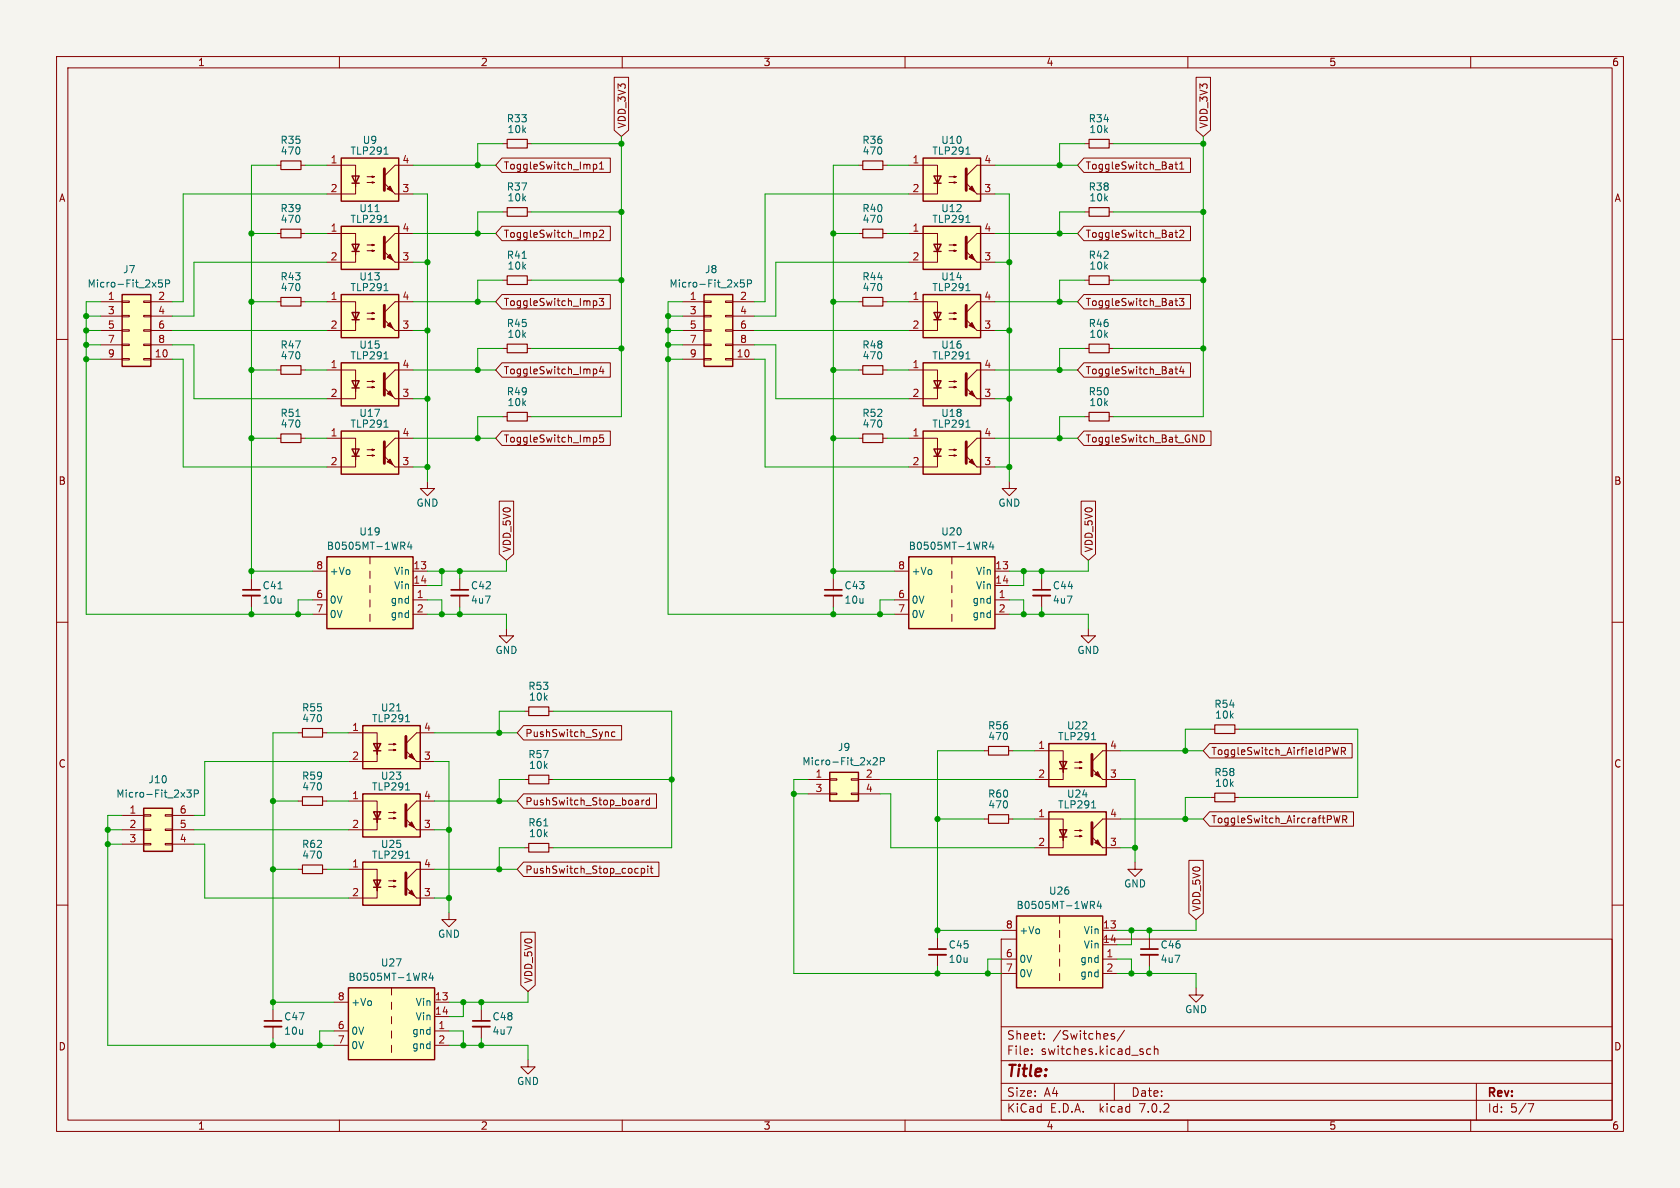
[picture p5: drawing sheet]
<svg xmlns="http://www.w3.org/2000/svg" width="297mm" height="210mm" viewBox="0 0 297 210" stroke-linecap="round" stroke-linejoin="round" font-family="sans-serif">
<defs><g id="words">
<text font-size="2.8" fill="#840000" x="178" y="190.8">Title:</text>
<g font-size="2.1" fill="#840000">
<text x="178" y="183.9">Sheet:</text>
<text x="186.2" y="183.9">/Switches/</text>
<text x="178" y="186.6">File:</text>
<text x="184" y="186.6">switches.kicad_sch</text>
<text x="178" y="196.8">KiCad</text>
<text x="178" y="194">Size:</text>
<text x="184.6" y="194">A4</text>
<text x="185.7" y="196.8">E.D.A.</text>
<text x="194.4" y="196.8">kicad</text>
<text x="200" y="194">Date:</text>
<text x="201.5" y="196.8">7.0.2</text>
<text x="263" y="194.2">Rev:</text>
<text x="263" y="196.8">Id:</text>
<text x="267" y="196.8">5/7</text>
</g>
<g font-size="1.8" fill="#840000">
<text x="35" y="11.8">1</text>
<text x="85" y="11.8">2</text>
<text x="135" y="11.8">3</text>
<text x="185" y="11.8">4</text>
<text x="235" y="11.8">5</text>
<text x="285" y="11.8">6</text>
<text x="110.8" y="22.7" transform="rotate(-90 110.8 22.7)">VDD_3V3</text>
<text x="213.6" y="22.7" transform="rotate(-90 213.6 22.7)">VDD_3V3</text>
<text x="10.4" y="35.8">A</text>
<text x="89.1" y="30.1">ToggleSwitch_Imp1</text>
<text x="191.9" y="30.1">ToggleSwitch_Bat1</text>
<text x="285.4" y="35.8">A</text>
<text x="89.1" y="42.2">ToggleSwitch_Imp2</text>
<text x="191.9" y="42.2">ToggleSwitch_Bat2</text>
<text x="89.1" y="54.3">ToggleSwitch_Imp3</text>
<text x="191.9" y="54.3">ToggleSwitch_Bat3</text>
<text x="89.1" y="66.3">ToggleSwitch_Imp4</text>
<text x="191.9" y="66.3">ToggleSwitch_Bat4</text>
<text x="89.1" y="78.4">ToggleSwitch_Imp5</text>
<text x="191.9" y="78.4">ToggleSwitch_Bat_GND</text>
<text x="10.3" y="85.8">B</text>
<text x="285.3" y="85.8">B</text>
<text x="90.5" y="97.6" transform="rotate(-90 90.5 97.6)">VDD_5V0</text>
<text x="193.3" y="97.6" transform="rotate(-90 193.3 97.6)">VDD_5V0</text>
<text x="92.9" y="130.5">PushSwitch_Sync</text>
<text x="10.3" y="135.8">C</text>
<text x="214.2" y="133.6">ToggleSwitch_AirfieldPWR</text>
<text x="285.3" y="135.8">C</text>
<text x="92.9" y="142.5">PushSwitch_Stop_board</text>
<text x="214.2" y="145.7">ToggleSwitch_AircraftPWR</text>
<text x="92.9" y="154.6">PushSwitch_Stop_cocpit</text>
<text x="212.4" y="161.1" transform="rotate(-90 212.4 161.1)">VDD_5V0</text>
<text x="94.3" y="173.8" transform="rotate(-90 94.3 173.8)">VDD_5V0</text>
<text x="10.3" y="185.8">D</text>
<text x="285.3" y="185.8">D</text>
<text x="35" y="199.8">1</text>
<text x="85" y="199.8">2</text>
<text x="135" y="199.8">3</text>
<text x="185" y="199.8">4</text>
<text x="235" y="199.8">5</text>
<text x="285" y="199.8">6</text>
</g>
<g font-size="1.8" fill="#006464">
<text x="89.5" y="21.8">R33</text>
<text x="89.7" y="23.7">10k</text>
<text x="192.4" y="21.8">R34</text>
<text x="192.5" y="23.7">10k</text>
<text x="49.5" y="25.6">R35</text>
<text x="49.6" y="27.5">470</text>
<text x="61.9" y="27.5">TLP291</text>
<text x="64.1" y="25.6">U9</text>
<text x="152.4" y="25.6">R36</text>
<text x="152.4" y="27.5">470</text>
<text x="164.8" y="27.5">TLP291</text>
<text x="166.3" y="25.6">U10</text>
<text x="89.5" y="33.8">R37</text>
<text x="89.7" y="35.8">10k</text>
<text x="192.4" y="33.8">R38</text>
<text x="192.5" y="35.8">10k</text>
<text x="49.5" y="37.7">R39</text>
<text x="49.6" y="39.6">470</text>
<text x="61.9" y="39.6">TLP291</text>
<text x="63.5" y="37.7">U11</text>
<text x="152.4" y="37.7">R40</text>
<text x="152.4" y="39.6">470</text>
<text x="164.8" y="39.6">TLP291</text>
<text x="166.3" y="37.7">U12</text>
<text x="89.5" y="45.9">R41</text>
<text x="89.7" y="47.8">10k</text>
<text x="192.4" y="45.9">R42</text>
<text x="192.5" y="47.8">10k</text>
<text x="15.4" y="51">Micro-Fit_2x5P</text>
<text x="21.7" y="48.5">J7</text>
<text x="49.5" y="49.7">R43</text>
<text x="49.6" y="51.6">470</text>
<text x="61.9" y="51.6">TLP291</text>
<text x="63.5" y="49.7">U13</text>
<text x="118.3" y="51">Micro-Fit_2x5P</text>
<text x="124.6" y="48.5">J8</text>
<text x="152.4" y="49.7">R44</text>
<text x="152.4" y="51.6">470</text>
<text x="164.8" y="51.6">TLP291</text>
<text x="166.3" y="49.7">U14</text>
<text x="89.5" y="58">R45</text>
<text x="89.7" y="59.9">10k</text>
<text x="192.4" y="58">R46</text>
<text x="192.5" y="59.9">10k</text>
<text x="49.5" y="61.8">R47</text>
<text x="49.6" y="63.7">470</text>
<text x="61.9" y="63.7">TLP291</text>
<text x="63.5" y="61.8">U15</text>
<text x="152.4" y="61.8">R48</text>
<text x="152.4" y="63.7">470</text>
<text x="164.8" y="63.7">TLP291</text>
<text x="166.3" y="61.8">U16</text>
<text x="89.5" y="70">R49</text>
<text x="89.7" y="71.9">10k</text>
<text x="192.4" y="70">R50</text>
<text x="192.5" y="71.9">10k</text>
<text x="49.5" y="73.9">R51</text>
<text x="49.6" y="75.8">470</text>
<text x="61.9" y="75.8">TLP291</text>
<text x="63.5" y="73.9">U17</text>
<text x="152.4" y="73.9">R52</text>
<text x="152.4" y="75.8">470</text>
<text x="164.8" y="75.8">TLP291</text>
<text x="166.3" y="73.9">U18</text>
<text x="73.6" y="89.7">GND</text>
<text x="176.4" y="89.7">GND</text>
<text x="63.5" y="94.8">U19</text>
<text x="166.3" y="94.8">U20</text>
<text x="57.7" y="97.3">B0505MT-1WR4</text>
<text x="58.3" y="101.8">+Vo</text>
<text x="69.5" y="101.8">Vin</text>
<text x="160.6" y="97.3">B0505MT-1WR4</text>
<text x="161.2" y="101.8">+Vo</text>
<text x="172.4" y="101.8">Vin</text>
<text x="46.4" y="104.3">C41</text>
<text x="46.4" y="106.9">10u</text>
<text x="58.3" y="106.9">0V</text>
<text x="68.9" y="106.9">gnd</text>
<text x="69.5" y="104.3">Vin</text>
<text x="83.2" y="104.3">C42</text>
<text x="83.2" y="106.9">4u7</text>
<text x="149.2" y="104.3">C43</text>
<text x="149.2" y="106.9">10u</text>
<text x="161.2" y="106.9">0V</text>
<text x="171.8" y="106.9">gnd</text>
<text x="172.4" y="104.3">Vin</text>
<text x="186.1" y="104.3">C44</text>
<text x="186.1" y="106.9">4u7</text>
<text x="58.3" y="109.4">0V</text>
<text x="68.9" y="109.4">gnd</text>
<text x="161.2" y="109.4">0V</text>
<text x="171.8" y="109.4">gnd</text>
<text x="87.5" y="115.8">GND</text>
<text x="190.4" y="115.8">GND</text>
<text x="53.3" y="125.9">R55</text>
<text x="67.3" y="125.9">U21</text>
<text x="93.3" y="122.1">R53</text>
<text x="93.5" y="124">10k</text>
<text x="214.6" y="125.3">R54</text>
<text x="53.4" y="127.8">470</text>
<text x="65.7" y="127.8">TLP291</text>
<text x="174.6" y="129.1">R56</text>
<text x="174.7" y="131">470</text>
<text x="187" y="131">TLP291</text>
<text x="188.6" y="129.1">U22</text>
<text x="214.7" y="127.2">10k</text>
<text x="53.3" y="138">R59</text>
<text x="67.3" y="138">U23</text>
<text x="93.3" y="134.2">R57</text>
<text x="93.5" y="136.1">10k</text>
<text x="141.8" y="135.4">Micro-Fit_2x2P</text>
<text x="148.1" y="132.9">J9</text>
<text x="214.6" y="137.4">R58</text>
<text x="20.5" y="141.2">Micro-Fit_2x3P</text>
<text x="26.2" y="138.6">J10</text>
<text x="53.4" y="139.9">470</text>
<text x="65.7" y="139.9">TLP291</text>
<text x="174.6" y="141.2">R60</text>
<text x="174.7" y="143.1">470</text>
<text x="187" y="143.1">TLP291</text>
<text x="188.6" y="141.2">U24</text>
<text x="214.7" y="139.3">10k</text>
<text x="93.3" y="146.2">R61</text>
<text x="93.5" y="148.1">10k</text>
<text x="53.3" y="150.1">R62</text>
<text x="53.4" y="152">470</text>
<text x="65.7" y="152">TLP291</text>
<text x="67.3" y="150.1">U25</text>
<text x="179.6" y="160.8">B0505MT-1WR4</text>
<text x="185.4" y="158.3">U26</text>
<text x="198.7" y="157">GND</text>
<text x="77.4" y="165.9">GND</text>
<text x="167.6" y="167.8">C45</text>
<text x="180.2" y="165.3">+Vo</text>
<text x="191.5" y="165.3">Vin</text>
<text x="191.5" y="167.8">Vin</text>
<text x="205.1" y="167.8">C46</text>
<text x="61.5" y="173.5">B0505MT-1WR4</text>
<text x="67.3" y="171">U27</text>
<text x="167.6" y="170.4">10u</text>
<text x="180.2" y="170.4">0V</text>
<text x="180.2" y="172.9">0V</text>
<text x="190.9" y="170.4">gnd</text>
<text x="190.9" y="172.9">gnd</text>
<text x="205.1" y="170.4">4u7</text>
<text x="62.1" y="178">+Vo</text>
<text x="73.4" y="178">Vin</text>
<text x="209.5" y="179.3">GND</text>
<text x="50.2" y="180.5">C47</text>
<text x="50.2" y="183.1">10u</text>
<text x="62.1" y="183.1">0V</text>
<text x="62.1" y="185.6">0V</text>
<text x="72.8" y="183.1">gnd</text>
<text x="72.8" y="185.6">gnd</text>
<text x="73.4" y="180.5">Vin</text>
<text x="87" y="180.5">C48</text>
<text x="87" y="183.1">4u7</text>
<text x="91.3" y="192">GND</text>
</g>
<g font-size="1.8" fill="#a90000">
<text x="58.4" y="29">1</text>
<text x="71.1" y="29">4</text>
<text x="161.3" y="29">1</text>
<text x="174" y="29">4</text>
<text x="58.4" y="34">2</text>
<text x="71.1" y="34">3</text>
<text x="161.3" y="34">2</text>
<text x="174" y="34">3</text>
<text x="58.4" y="41">1</text>
<text x="71.1" y="41">4</text>
<text x="161.3" y="41">1</text>
<text x="174" y="41">4</text>
<text x="58.4" y="46.1">2</text>
<text x="71.1" y="46.1">3</text>
<text x="161.3" y="46.1">2</text>
<text x="174" y="46.1">3</text>
<text x="19" y="53.1">1</text>
<text x="27.9" y="53.1">2</text>
<text x="58.4" y="53.1">1</text>
<text x="71.1" y="53.1">4</text>
<text x="121.9" y="53.1">1</text>
<text x="130.8" y="53.1">2</text>
<text x="161.3" y="53.1">1</text>
<text x="174" y="53.1">4</text>
<text x="19" y="55.6">3</text>
<text x="19" y="58.2">5</text>
<text x="27.9" y="55.6">4</text>
<text x="27.9" y="58.2">6</text>
<text x="58.4" y="58.2">2</text>
<text x="71.1" y="58.2">3</text>
<text x="121.9" y="55.6">3</text>
<text x="121.9" y="58.2">5</text>
<text x="130.8" y="55.6">4</text>
<text x="130.8" y="58.2">6</text>
<text x="161.3" y="58.2">2</text>
<text x="174" y="58.2">3</text>
<text x="19" y="60.7">7</text>
<text x="19" y="63.2">9</text>
<text x="27.3" y="63.2">10</text>
<text x="27.9" y="60.7">8</text>
<text x="58.4" y="65.2">1</text>
<text x="71.1" y="65.2">4</text>
<text x="121.9" y="60.7">7</text>
<text x="121.9" y="63.2">9</text>
<text x="130.2" y="63.2">10</text>
<text x="130.8" y="60.7">8</text>
<text x="161.3" y="65.2">1</text>
<text x="174" y="65.2">4</text>
<text x="58.4" y="70.2">2</text>
<text x="71.1" y="70.2">3</text>
<text x="161.3" y="70.2">2</text>
<text x="174" y="70.2">3</text>
<text x="58.4" y="77.2">1</text>
<text x="71.1" y="77.2">4</text>
<text x="161.3" y="77.2">1</text>
<text x="174" y="77.2">4</text>
<text x="58.4" y="82.3">2</text>
<text x="71.1" y="82.3">3</text>
<text x="161.3" y="82.3">2</text>
<text x="174" y="82.3">3</text>
<text x="55.8" y="100.7">8</text>
<text x="73" y="100.7">13</text>
<text x="158.7" y="100.7">8</text>
<text x="175.9" y="100.7">13</text>
<text x="55.8" y="105.8">6</text>
<text x="73" y="103.3">14</text>
<text x="73.6" y="105.8">1</text>
<text x="158.7" y="105.8">6</text>
<text x="175.9" y="103.3">14</text>
<text x="176.5" y="105.8">1</text>
<text x="55.8" y="108.3">7</text>
<text x="73.6" y="108.3">2</text>
<text x="158.7" y="108.3">7</text>
<text x="176.5" y="108.3">2</text>
<text x="62.2" y="129.3">1</text>
<text x="74.9" y="129.3">4</text>
<text x="62.2" y="134.4">2</text>
<text x="74.9" y="134.4">3</text>
<text x="144.1" y="137.5">1</text>
<text x="153" y="137.5">2</text>
<text x="183.5" y="132.5">1</text>
<text x="183.5" y="137.5">2</text>
<text x="196.2" y="137.5">3</text>
<text x="196.2" y="132.5">4</text>
<text x="22.8" y="143.9">1</text>
<text x="31.7" y="143.9">6</text>
<text x="62.2" y="141.4">1</text>
<text x="74.9" y="141.4">4</text>
<text x="144.1" y="140.1">3</text>
<text x="153" y="140.1">4</text>
<text x="22.8" y="146.4">2</text>
<text x="22.8" y="149">3</text>
<text x="31.7" y="149">4</text>
<text x="31.7" y="146.4">5</text>
<text x="62.2" y="146.4">2</text>
<text x="74.9" y="146.4">3</text>
<text x="183.5" y="144.5">1</text>
<text x="183.5" y="149.6">2</text>
<text x="196.2" y="149.6">3</text>
<text x="196.2" y="144.5">4</text>
<text x="62.2" y="153.4">1</text>
<text x="74.9" y="153.4">4</text>
<text x="62.2" y="158.5">2</text>
<text x="74.9" y="158.5">3</text>
<text x="177.8" y="164.2">8</text>
<text x="194.9" y="164.2">13</text>
<text x="194.9" y="166.8">14</text>
<text x="177.8" y="169.3">6</text>
<text x="177.8" y="171.8">7</text>
<text x="195.5" y="169.3">1</text>
<text x="195.5" y="171.8">2</text>
<text x="59.7" y="176.9">8</text>
<text x="76.8" y="176.9">13</text>
<text x="76.8" y="179.5">14</text>
<text x="59.7" y="182">6</text>
<text x="59.7" y="184.5">7</text>
<text x="77.4" y="182">1</text>
<text x="77.4" y="184.5">2</text>
</g>
</g></defs>
<path d="M0 0h297v210h-297z" fill="#f5f4ef" stroke="#f5f4ef" stroke-width=".18"/>
<g fill="none" stroke="#840000" stroke-width=".18">
<path d="M10 10h277v190h-277zM12 12h273v186h-273zM60 10v2M108.6 13.7h2.5v9.3l-1.2 1.1-1.3-1.1zM110 10v2M160 10v2M210 10v2M211.5 13.7h2.5v9.3l-1.3 1.1-1.2-1.1zM260 10v2M48.9 29.2h.8M53.2 29.2h.8M57.8 29.2h5.1v3.8v-1.9"/>
<path d="M62.9 32.4v1.9h-5.1M64.9 32.3h1.3l-.4 .1v-.3l.4 .2M64.9 31.2h1.3l-.4 .2v-.3l.4 .1M69.8 34.3h3.2M73 29.2h-3.2l-1.9 1.9M88.7 27.9h19.2v2.6h-19.2l-1.1-1.3zM88.9 37.5h.8M88.9 25.4h.8M93.2 37.5h.8M93.2 25.4h.8M104.9 29.1l.4-.1 .2 .3-.1 .5h-.5M104.9 29v1.3"/>
<path d="M106 29.9h.7M106 29l.4-.4v1.3M151.8 29.2h.7M156.1 29.2h.7M160.7 29.2h5v3.8v-1.9M165.7 32.4v1.9h-5M167.8 32.3h1.2l-.3 .1v-.3l.3 .2M167.8 31.2h1.2l-.3 .2v-.3l.3 .1M172.7 34.3h3.2M175.9 29.2h-3.2l-1.9 1.9M191.6 27.9h18.9v2.6h-18.9l-1.1-1.3zM191.8 37.5h.7"/>
<path d="M191.8 25.4h.7M196.1 37.5h.7M196.1 25.4h.7M207.7 29h.5M207.9 28.6v1.1l.3 .2M208.6 29.9h.7M208.6 29l.3-.4v1.3M10 60h2M17.8 53.3h3.8M17.8 55.9h3.8M17.8 58.4h3.8M21.6 58.3h1.3v.2h-1.3z"/>
<path d="M21.6 55.8h1.3v.2h-1.3zM21.6 53.2h1.3v.3h-1.3zM25.4 58.3h1.3v.2h-1.3zM25.4 55.8h1.3v.2h-1.3zM25.4 53.2h1.3v.3h-1.3zM26.7 53.3h3.8M26.7 55.9h3.8M26.7 58.4h3.8M48.9 53.3h.8M48.9 41.3h.8M53.2 53.3h.8M53.2 41.3h.8"/>
<path d="M57.8 53.3h5.1v3.9v-2M57.8 41.3h5.1v3.8v-1.9M62.9 56.5v1.9h-5.1M62.9 44.5v1.9h-5.1M64.9 56.4h1.3l-.4 .1v-.2l.4 .1M64.9 55.4h1.3l-.4 .1v-.3l.4 .2M64.9 44.3h1.3l-.4 .2v-.3l.4 .1M64.9 43.3h1.3l-.4 .1v-.2l.4 .1M69.8 58.4h3.2M69.8 46.4h3.2M73 53.3h-3.2l-1.9 1.9M73 41.3h-3.2l-1.9 1.9"/>
<path d="M88.7 40h19.2v2.5h-19.2l-1.1-1.2zM88.7 52.1h19.2v2.5h-19.2l-1.1-1.3zM88.9 49.5h.8M93.2 49.5h.8M105 41.1l.4 .1 .1 .1-.1 .5-.4 .2M105 53.2h.4l.1 .2-.1 .5-.4 .1M105.9 52.7h.8l-.4 .5 .4 .2v.5l-.2 .1-.6-.1M106 40.8l.5-.1 .2 .3-.8 1h.8M120.6 53.3h3.9M120.6 55.9h3.9M120.6 58.4h3.9M124.5 58.3h1.2v.2h-1.2z"/>
<path d="M124.5 55.8h1.2v.2h-1.2zM124.5 53.2h1.2v.3h-1.2zM128.3 58.3h1.2v.2h-1.2zM128.3 55.8h1.2v.2h-1.2zM128.3 53.2h1.2v.3h-1.2zM129.5 53.3h3.8M129.5 55.9h3.8M129.5 58.4h3.8M151.8 53.3h.7M151.8 41.3h.7M156.1 53.3h.7M156.1 41.3h.7"/>
<path d="M160.7 41.3h5v3.8v-1.9M160.7 53.3h5v3.9v-2M165.7 44.5v1.9h-5M165.7 56.5v1.9h-5M167.8 44.3h1.2l-.3 .2v-.3l.3 .1M167.8 43.3h1.2l-.3 .1v-.2l.3 .1M167.8 56.4h1.2l-.3 .1v-.2l.3 .1M167.8 55.4h1.2l-.3 .1v-.3l.3 .2M172.7 58.4h3.2M172.7 46.4h3.2M175.9 53.3h-3.2l-1.9 1.9M175.9 41.3h-3.2l-1.9 1.9"/>
<path d="M191.6 40h18.9v2.5h-18.9l-1.1-1.2zM191.6 52.1h18.9v2.5h-18.9l-1.1-1.3zM191.8 49.5h.7M196.1 49.5h.7M207.7 41.1h.5M207.7 53.2h.5M207.9 40.7v1.1l.3 .2M207.9 52.7v1.1l.3 .2M208.5 52.7h.8l-.4 .5 .3 .2v.5l-.2 .1-.5-.1M208.6 40.8l.4-.1 .3 .3-.8 1h.8M285 60h2M17.8 63.5h3.8"/>
<path d="M17.8 61h3.8M21.6 63.4h1.3v.2h-1.3zM21.6 60.8h1.3v.3h-1.3zM25.4 63.4h1.3v.2h-1.3zM25.4 60.8h1.3v.3h-1.3zM26.7 63.5h3.8M26.7 61h3.8M48.9 77.5h.8M48.9 65.4h.8M53.2 77.5h.8M53.2 65.4h.8M57.8 77.5h5.1v3.8v-1.9"/>
<path d="M57.8 65.4h5.1v3.8v-1.9M62.9 68.6v1.9h-5.1M64.9 79.5h1.3l-.4 .1v-.2l.4 .1M64.9 68.5h1.3l-.4 .1v-.3l.4 .2M64.9 67.4h1.3l-.4 .2v-.3l.4 .1M69.8 70.5h3.2M73 77.5h-3.2l-1.9 1.9M73 65.4h-3.2l-1.9 1.9M88.7 64.1h19.2v2.6h-19.2l-1.1-1.3zM88.7 76.2h19.2v2.5h-19.2l-1.1-1.2zM88.9 73.7h.8M88.9 61.6h.8"/>
<path d="M93.2 73.7h.8M93.2 61.6h.8M105 65.2l.4 .1 .1 .2-.1 .5-.4 .1M105 77.3l.4 .1 .1 .1-.1 .5-.4 .1M106.3 64.8l-.3 .9h.8M106.6 65.2v.9M106.7 76.9h-.6l-.1 .6 .2-.1h.4l.1 .2v.4l-.2 .1-.5-.1M120.6 63.5h3.9M120.6 61h3.9M124.5 63.4h1.2v.2h-1.2zM124.5 60.8h1.2v.3h-1.2zM128.3 63.4h1.2v.2h-1.2z"/>
<path d="M128.3 60.8h1.2v.3h-1.2zM129.5 63.5h3.8M129.5 61h3.8M151.8 77.5h.7M151.8 65.4h.7M156.1 77.5h.7M156.1 65.4h.7M160.7 77.5h5v3.8v-1.9M160.7 65.4h5v3.8v-1.9M165.7 68.6v1.9h-5M167.8 79.5h1.2l-.3 .1v-.2l.3 .1M167.8 68.5h1.2l-.3 .1v-.3l.3 .2"/>
<path d="M167.8 67.4h1.2l-.3 .2v-.3l.3 .1M172.7 70.5h3.2M175.9 77.5h-3.2l-1.9 1.9M175.9 65.4h-3.2l-1.9 1.9M191.6 64.1h18.9v2.6h-18.9l-1.1-1.3zM191.6 76.2h22.5v2.5h-22.5l-1.1-1.2zM191.8 73.7h.7M191.8 61.6h.7M196.1 73.7h.7M196.1 61.6h.7M207.7 65.2h.5M207.9 64.8v1.1l.3 .2"/>
<path d="M208.9 64.8l-.3 .9h.7M209.2 65.2v.9M212.2 76.9a.64 .64 0 0 1 .7 .6 .64 .64 0 0 1-.7 .6zM62.9 80.6v2h-5.1M64.9 80.5h1.3l-.4 .1v-.2l.4 .1M65.4 98.4v1.3M69.8 82.6h3.2M75.6 85.1v1.3h1.2l-1.2 1.2-1.3-1.2h1.3M88.3 88.6h2.5v9.3l-1.3 1.2-1.2-1.2zM165.7 80.6v2h-5M167.8 80.5h1.2l-.3 .1v-.2l.3 .1M168.3 98.4v1.3"/>
<path d="M172.7 82.6h3.2M178.4 85.1v1.3h1.3l-1.3 1.2-1.2-1.2h1.2M191.1 88.6h2.6v9.3l-1.3 1.2-1.3-1.2zM10 110h2M44.4 102.2v2.1M44.4 105.3v2M55.2 106h2.6M55.2 101h2.6M55.2 108.6h2.6M65.4 101v1.2M65.4 103.5v1.3M65.4 106v1.3"/>
<path d="M65.4 108.6v1.3M73 106h2.6M73 101h2.6M73 103.5h2.6M73 108.6h2.6M81.3 102.2v2.1M81.3 105.3v2M89.5 111.1v1.3h1.3l-1.3 1.3-1.2-1.3h1.2M147.3 102.2v2.1M147.3 105.3v2M158.1 106h2.6M158.1 101h2.6"/>
<path d="M158.1 108.6h2.6M168.3 101v1.2M168.3 103.5v1.3M168.3 106v1.3M168.3 108.6v1.3M175.9 106h2.5M175.9 101h2.5M175.9 103.5h2.5M175.9 108.6h2.5M184.1 102.2v2.1M184.1 105.3v2M192.4 111.1v1.3h1.3l-1.3 1.3-1.3-1.3h1.3"/>
<path d="M285 110h2M52.7 129.5h.8M57 129.5h.8M61.6 129.5h5.1v3.9v-2M66.7 132.7v1.9h-5.1M68.7 132.6h1.3l-.4 .1v-.2l.4 .1M68.7 131.6h1.3l-.4 .1v-.3l.4 .2M73.7 134.6h3.1M76.8 129.5h-3.1l-1.9 1.9M92.6 128.3h17.3v2.5h-17.3l-1.2-1.3zM92.7 137.8h.8M92.7 125.7h.8"/>
<path d="M97 137.8h.8M97 125.7h.8M108.7 129.4h-.3l-.3 .2 .1 .6h.5M142.9 137.8h3.8M146.7 137.7h1.3v.2h-1.3zM150.5 137.7h1.3v.2h-1.3zM151.8 137.8h3.8M174 132.7h.8M178.3 132.7h.8M182.9 132.7h5.1v3.8v-1.9M188 135.9v1.9h-5.1M190 135.8h1.3l-.4 .1v-.3l.4 .2"/>
<path d="M190 134.7h1.3l-.4 .2v-.3l.4 .1M194.9 137.8h3.2M198.1 132.7h-3.2l-1.9 1.9M213.8 131.4h25.2v2.6h-25.2l-1.1-1.3zM214 128.9h.8M218.3 128.9h.8M235.6 132.1l.3 1.3 .2-.9 .2 .9 .4-1.3M237.1 132.8l.6-.1 .2-.2-.1-.3-.7-.1v1.3M237.4 132.8l.5 .6M10 160h2M21.6 144.1h3.8M21.6 146.7h3.8"/>
<path d="M21.6 149.2h3.8M25.4 149.1h1.3v.3h-1.3zM25.4 146.6h1.3v.2h-1.3zM25.4 144h1.3v.3h-1.3zM29.2 149.1h1.3v.3h-1.3zM29.2 146.6h1.3v.2h-1.3zM29.2 144h1.3v.3h-1.3zM30.5 144.1h3.8M30.5 146.7h3.8M30.5 149.2h3.8M52.7 141.6h.8M52.7 153.7h.8"/>
<path d="M57 141.6h.8M57 153.7h.8M61.6 153.7h5.1v3.8v-1.9M61.6 141.6h5.1v3.8v-1.9M66.7 156.8v2h-5.1M66.7 144.8v1.9h-5.1M68.7 156.7h1.3l-.4 .1v-.2l.4 .1M68.7 155.7h1.3l-.4 .1v-.2l.4 .1M68.7 144.7h1.3l-.4 .1v-.3l.4 .2M68.7 143.6h1.3l-.4 .2v-.3l.4 .1M73.7 146.7h3.1M73.7 158.8h3.1"/>
<path d="M76.8 141.6h-3.1l-1.9 1.9M76.8 153.7h-3.1l-1.9 1.9M92.6 152.4h23.9v2.5h-23.9l-1.2-1.2zM92.6 140.3h23.5v2.6h-23.5l-1.2-1.3zM92.7 149.9h.8M97 149.9h.8M112.7 141.4l.2 .2v.7M112.9 142.2l-.4 .1M112.9 141.7l-.4 .1M113.4 153.5v1.3M113.4 153.6l.3-.1 .3 .2-.1 .6h-.5M113.5 141.4v.9"/>
<path d="M113.9 141.4l-.4 .3M114.5 153.1v.1M114.5 153.5v.8M114.8 141.5l-.3-.1-.3 .3 .1 .5h.5M114.8 141v1.3M114.9 153.5h.5M115.1 153.1v1.1l.3 .1M142.9 140.3h3.8M146.7 140.2h1.3v.3h-1.3zM150.5 140.2h1.3v.3h-1.3zM151.8 140.3h3.8M174 144.8h.8"/>
<path d="M178.3 144.8h.8M182.9 144.8h5.1v3.8v-1.9M188 148v1.9h-5.1M190 147.8h1.3l-.4 .2v-.3l.4 .1M190 146.8h1.3l-.4 .1v-.2l.4 .1M194.9 149.9h3.2M198.1 144.8h-3.2l-1.9 1.9M200.7 152.4v1.3h1.2l-1.2 1.2-1.3-1.2h1.3M210.2 152.1h2.5v9.3l-1.2 1.2-1.3-1.2zM213.8 143.5h25.5v2.6h-25.5l-1.1-1.3zM214 141h.8M218.3 141h.8"/>
<path d="M235.8 144.2l.3 1.3 .2-.9 .3 .9 .3-1.3M237.4 144.9l.6-.1 .1-.2-.1-.3-.6-.1v1.3M237.7 144.9l.4 .6M285 160h2M48.3 178.4v2.1M59.1 177.2h2.5M69.2 174.6v1.3M69.2 177.2v1.2M69.2 179.7v1.3M76.8 177.2h2.6M76.8 179.7h2.6M79.4 161.3v1.3h1.2l-1.2 1.2-1.3-1.2h1.3"/>
<path d="M85.1 178.4v2.1M92.1 164.8h2.5v9.3l-1.3 1.2-1.2-1.2zM165.7 165.7v2.1M165.7 168.8v2M177 166h108v32h-108zM177.2 169.5h2.5M177.2 164.5h2.5M177.2 172.1h2.5M187.3 161.9v1.3M187.3 164.5v1.2M187.3 167v1.3M187.3 169.5v1.3"/>
<path d="M187.3 172.1v1.3M194.9 169.5h2.6M194.9 164.5h2.6M194.9 167h2.6M194.9 172.1h2.6M203.2 165.7v2.1M203.2 168.8v2M211.5 174.6v1.3h1.2l-1.2 1.3-1.3-1.3h1.3M48.3 181.5v2M59.1 182.2h2.5M59.1 184.8h2.5M60 198v2"/>
<path d="M69.2 182.2v1.3M69.2 184.8v1.3M76.8 182.2h2.6M76.8 184.8h2.6M85.1 181.5v2M93.3 187.3v1.3h1.3l-1.3 1.3-1.2-1.3h1.2M110 198v2M160 198v2M177 194.5h108M177 191.5h108M177 187.5h108M177 181.5h108"/>
<path d="M182.4 186.3v.1M182.4 185.5v.1M184.6 183.6v.1M184.6 182.8v.1M196.4 183l.7 .4-.2 .3-.5-.1M197 182.8l-.4-.1-.2 .2M197 191.5v3M198.8 182.1l-1.3 2M203.4 185.5l-.4-.1-.3 .3v.4l.2 .2h.5M204.1 185.5l.2-.1 .3 .1 .1 .9M204.1 184.9v1.5M210 198v2"/>
<path d="M260 198v2M261 191.5v6.5M270.1 195.1h1l-.6 1.5"/>
</g>
<g fill="none" stroke="#840000" stroke-width=".2">
<path d="M49.7 28.4h3.5v1.6h-3.5zM89.7 36.7h3.5v1.5h-3.5zM89.7 24.6h3.5v1.6h-3.5zM152.5 28.4h3.6v1.6h-3.6zM192.5 36.7h3.6v1.5h-3.6zM192.5 24.6h3.6v1.6h-3.6zM49.7 52.6h3.5v1.5h-3.5zM49.7 40.5h3.5v1.5h-3.5zM89.7 48.8h3.5v1.5h-3.5zM152.5 52.6h3.6v1.5h-3.6zM152.5 40.5h3.6v1.5h-3.6zM192.5 48.8h3.6v1.5h-3.6z"/>
<path d="M49.7 64.6h3.5v1.6h-3.5zM49.7 76.7h3.5v1.5h-3.5zM89.7 72.9h3.5v1.5h-3.5zM89.7 60.8h3.5v1.6h-3.5zM152.5 76.7h3.6v1.5h-3.6zM152.5 64.6h3.6v1.6h-3.6zM192.5 72.9h3.6v1.5h-3.6zM192.5 60.8h3.6v1.6h-3.6zM53.5 128.8h3.5v1.5h-3.5zM93.5 137h3.5v1.6h-3.5zM93.5 125h3.5v1.5h-3.5zM174.8 132h3.5v1.5h-3.5z"/>
<path d="M214.8 128.1h3.5v1.6h-3.5zM53.5 140.8h3.5v1.6h-3.5zM53.5 152.9h3.5v1.5h-3.5zM93.5 149.1h3.5v1.5h-3.5zM174.8 144h3.5v1.5h-3.5zM214.8 140.2h3.5v1.5h-3.5z"/>
</g>
<g fill="#ffffc2" stroke="#ffffc2" stroke-width=".18">
<path d="M185.4 131.4h10.2v7.7h-10.2z"/>
<path d="M185.4 143.5h10.2v7.6h-10.2z"/>
<path d="M146.7 136.5h5.1v5.1h-5.1z"/>
<path d="M124.5 52.1h5v12.7h-5z"/>
<path d="M163.2 76.2h10.2v7.6h-10.2z"/>
<path d="M163.2 27.9h10.2v7.7h-10.2z"/>
<path d="M163.2 40h10.2v7.6h-10.2z"/>
<path d="M179.7 161.9h15.2v12.7h-15.2z"/>
<path d="M160.7 98.4h15.2v12.7h-15.2z"/>
<path d="M60.3 76.2h10.2v7.6h-10.2z"/>
<path d="M57.8 98.4h15.2v12.7h-15.2z"/>
<path d="M64.1 128.3h10.2v7.6h-10.2z"/>
<path d="M163.2 52.1h10.2v7.6h-10.2z"/>
<path d="M163.2 64.1h10.2v7.7h-10.2z"/>
<path d="M25.4 142.9h5.1v7.6h-5.1z"/>
<path d="M61.6 174.6h15.2v12.7h-15.2z"/>
<path d="M64.1 152.4h10.2v7.6h-10.2z"/>
<path d="M64.1 140.3h10.2v7.7h-10.2z"/>
<path d="M60.3 64.1h10.2v7.7h-10.2z"/>
<path d="M60.3 52.1h10.2v7.6h-10.2z"/>
<path d="M60.3 27.9h10.2v7.7h-10.2z"/>
<path d="M60.3 40h10.2v7.6h-10.2z"/>
<path d="M21.6 52.1h5.1v12.7h-5.1z"/>
</g>
<g fill="none" stroke="#840000" stroke-width=".25">
<path d="M60.3 27.9h10.2v7.7h-10.2zM62.2 31.1h1.3l-.6 1.3zM62.2 32.4h1.3M163.2 27.9h10.2v7.7h-10.2zM165.1 31.1h1.3l-.7 1.3zM165.1 32.4h1.3M21.6 52.1h5.1v12.7h-5.1zM60.3 52.1h10.2v7.6h-10.2zM60.3 40h10.2v7.6h-10.2zM62.2 55.2h1.3l-.6 1.3zM62.2 43.2h1.3l-.6 1.3zM62.2 44.5h1.3"/>
<path d="M62.2 56.5h1.3M124.5 52.1h5v12.7h-5zM163.2 40h10.2v7.6h-10.2zM163.2 52.1h10.2v7.6h-10.2zM165.1 43.2h1.3l-.7 1.3zM165.1 55.2h1.3l-.7 1.3zM165.1 44.5h1.3M165.1 56.5h1.3M60.3 76.2h10.2v7.6h-10.2zM60.3 64.1h10.2v7.7h-10.2zM62.2 79.4h1.3l-.6 1.2zM62.2 67.3h1.3l-.6 1.3z"/>
<path d="M62.2 68.6h1.3M163.2 76.2h10.2v7.6h-10.2zM163.2 64.1h10.2v7.7h-10.2zM165.1 79.4h1.3l-.7 1.2zM165.1 67.3h1.3l-.7 1.3zM165.1 68.6h1.3M57.8 98.4h15.2v12.7h-15.2zM62.2 80.6h1.3M160.7 98.4h15.2v12.7h-15.2zM165.1 80.6h1.3M64.1 128.3h10.2v7.6h-10.2zM66 131.4h1.3l-.6 1.3z"/>
<path d="M66 132.7h1.3M146.7 136.5h5.1v5.1h-5.1zM185.4 131.4h10.2v7.7h-10.2zM187.3 134.6h1.3l-.6 1.3zM187.3 135.9h1.3M25.4 142.9h5.1v7.6h-5.1zM64.1 152.4h10.2v7.6h-10.2zM64.1 140.3h10.2v7.7h-10.2zM66 155.6h1.3l-.6 1.2zM66 143.5h1.3l-.6 1.3zM66 156.8h1.3M66 144.8h1.3"/>
<path d="M185.4 143.5h10.2v7.6h-10.2zM187.3 146.7h1.3l-.6 1.3zM187.3 148h1.3M61.6 174.6h15.2v12.7h-15.2zM179.7 161.9h15.2v12.7h-15.2z"/>
</g>
<g fill="#840000" stroke="#840000" stroke-width=".18">
<path d="M193 135.9l1.9 1.9z"/>
<path d="M193.5 136.9l.6-.5 .5 1z"/>
<path d="M193 148l1.9 1.9z"/>
<path d="M193.5 149l.6-.5 .5 1z"/>
<path d="M170.8 80.6l1.9 2z"/>
<path d="M171.8 81.2l.5 1-1-.5z"/>
<path d="M170.8 32.4l1.9 1.9z"/>
<path d="M171.3 33.4l.5-.5 .5 1z"/>
<path d="M170.8 44.5l1.9 1.9z"/>
<path d="M171.8 45l.5 1-1-.5z"/>
<path d="M67.9 80.6l1.9 2z"/>
<path d="M68.5 81.7l.5-.5 .5 1z"/>
<path d="M71.8 132.7l1.9 1.9z"/>
<path d="M72.3 133.7l.5-.5 .5 1z"/>
<path d="M170.8 56.5l1.9 1.9z"/>
<path d="M171.8 57l.5 1-1-.5z"/>
<path d="M170.8 68.6l1.9 1.9z"/>
<path d="M171.8 69.1l.5 1-1-.5z"/>
<path d="M71.8 156.8l1.9 2z"/>
<path d="M72.3 157.9l.5-.5 .5 1z"/>
<path d="M71.8 144.8l1.9 1.9z"/>
<path d="M72.3 145.8l.5-.5 .5 1z"/>
<path d="M67.9 68.6l1.9 1.9z"/>
<path d="M68.5 69.6l.5-.5 .5 1z"/>
<path d="M67.9 56.5l1.9 1.9z"/>
<path d="M68.5 57.5l.5-.5 .5 1z"/>
<path d="M67.9 32.4l1.9 1.9z"/>
<path d="M68.5 33.4l.5-.5 .5 1z"/>
<path d="M67.9 44.5l1.9 1.9z"/>
<path d="M68.5 45.5l.5-.5 .5 1z"/>
</g>
<g fill="none" stroke="#840000" stroke-width=".51">
<path d="M67.9 29.8v3.9M170.8 29.8v3.9M67.9 54v3.8M67.9 41.9v3.8M170.8 41.9v3.8M170.8 54v3.8M67.9 78.1v3.8M67.9 66v3.9M170.8 78.1v3.8M170.8 66v3.9M71.8 130.2v3.8M193 133.4v3.8"/>
<path d="M71.8 154.3v3.8M71.8 142.2v3.9M193 145.4v3.8"/>
</g>
<g fill="none" stroke="#006464" stroke-width=".18">
<path d="M66.3 37.4h.7M67.9 27.3h.7M67.9 39.3h.7M170.8 27.3h.7M170.8 39.3h.7M28.7 49.5h-.6l-.1 .6 .2-.1h.4l.1 .2v.4l-.2 .2-.5-.2M29.3 50.1h.6l.1-.2-.1-.3-.6-.1v1.3M67.9 51.4h.7M131.5 49.5h-.6v.6l.2-.1h.4l.1 .2-.1 .4-.1 .2-.5-.2M132.1 50.1h.6l.2-.2-.1-.3-.7-.1v1.3M170.8 51.4h.7M67.9 75.5h.7"/>
<path d="M67.9 63.5h.7M170.8 75.5h.7M170.8 63.5h.7M71.2 96.5l.4 .6M71.5 95.9l.1 .2-.1 .3M72.4 95.8l-.3 .9h.7M72.7 96.3v.8M174 96.5l.4 .6M174.3 95.9l.1 .2-.1 .3M175.2 95.8l-.3 .9h.8M175.5 96.3v.8M33 139.7h.8l-.4 .4 .3 .2v.5l-.1 .1-.6-.1"/>
<path d="M70.1 125.7h.7M71.7 127.6h.7M71.7 139.7h.7M154.4 134.1l.4-.2 .3 .4-.8 .9h.8M155.6 134.6l.6-.1 .2-.1-.1-.3-.7-.2v1.3M193 130.8h.7M34.4 140.3h.6l.1-.2-.1-.3-.6-.1v1.2M71.7 151.7h.7M193 142.8h.7M193.4 159.4l.1 .2-.1 .3M194.3 159.3l-.3 .9h.8M194.6 159.8v.8"/>
<path d="M75 172.7l.4 .6M75.3 172.1l.1 .2-.1 .3M76.2 172l-.3 .9h.8M76.5 172.5v.8M193.1 160l.4 .6"/>
</g>
<path d="M42.9 105.3h3.1M79.8 105.3h3M145.8 105.3h3M182.6 105.3h3.1M164.2 168.8h3.1M201.7 168.8h3M46.7 181.5h3.1M83.6 181.5h3" fill="none" stroke="#840000" stroke-width=".33"/>
<path d="M42.9 104.3h3.1M79.8 104.3h3M145.8 104.3h3M182.6 104.3h3.1M164.2 167.8h3.1M201.7 167.8h3M46.7 180.5h3.1M83.6 180.5h3" fill="none" stroke="#840000" stroke-width=".3"/>
<g fill="none" stroke="#009600" stroke-width=".18">
<path d="M48.9 29.2h-4.5v73M54 29.2h3.8M57.8 34.3h-25.4v19h-1.9M73 34.3h2.6v50.8M73 29.2h14.6M88.9 25.4h-4.4v3.8M88.9 37.5h-4.4v3.8M94 37.5h15.9M94 25.4h15.9M109.9 24.1v49.6h-15.9M151.8 29.2h-4.5v73M156.8 29.2h3.9"/>
<path d="M160.7 34.3h-25.4v19h-2M175.9 34.3h2.5v50.8M175.9 29.2h14.6M191.8 25.4h-4.5v3.8M191.8 37.5h-4.5v3.8M196.8 37.5h15.9M196.8 25.4h15.9M212.7 24.1v49.6h-15.9M15.2 55.9h2.6M15.2 58.4h2.6M17.8 53.3h-2.6v55.3h40M30.5 58.4h27.3"/>
<path d="M44.4 41.3h4.5M44.4 53.3h4.5M54 41.3h3.8M54 53.3h3.8M57.8 46.4h-23.5v9.5h-3.8M73 41.3h14.6M73 53.3h14.6M73 58.4h2.6M73 46.4h2.6M88.9 49.5h-4.4v3.8M94 49.5h15.9M118.1 55.9h2.5"/>
<path d="M118.1 58.4h2.5M120.6 53.3h-2.5v55.3h40M133.3 58.4h27.4M147.3 41.3h4.5M147.3 53.3h4.5M156.8 41.3h3.9M156.8 53.3h3.9M160.7 46.4h-23.5v9.5h-3.9M175.9 41.3h14.6M175.9 53.3h14.6M175.9 58.4h2.5M175.9 46.4h2.5"/>
<path d="M191.8 49.5h-4.5v3.8M196.8 49.5h15.9M15.2 61h2.6M15.2 63.5h2.6M30.5 61h3.8v9.5h23.5M30.5 63.5h1.9v19.1h25.4M44.4 77.5h4.5M44.4 65.4h4.5M54 77.5h3.8M54 65.4h3.8M73 77.5h14.6M73 70.5h2.6"/>
<path d="M73 65.4h14.6M88.9 61.6h-4.4v3.8M88.9 73.7h-4.4v3.8M94 61.6h15.9M118.1 61h2.5M118.1 63.5h2.5M133.3 61h3.9v9.5h23.5M133.3 63.5h2v19.1h25.4M147.3 77.5h4.5M147.3 65.4h4.5M156.8 77.5h3.9M156.8 65.4h3.9"/>
<path d="M175.9 77.5h14.6M175.9 70.5h2.5M175.9 65.4h14.6M191.8 61.6h-4.5v3.8M191.8 73.7h-4.5v3.8M196.8 61.6h15.9M73 82.6h2.6M89.5 99.1v1.9h-13.9M175.9 82.6h2.5M192.4 99.1v1.9h-14M44.4 101h10.8M44.4 107.3v1.3"/>
<path d="M55.2 106h-2.5v2.6M75.6 108.6h13.9v2.5M75.6 106h2.5v2.6M78.1 101v2.5h-2.5M81.3 101v1.2M81.3 107.3v1.3M147.3 107.3v1.3M147.3 101h10.8M158.1 106h-2.5v2.6M178.4 108.6h14v2.5M178.4 106h2.6v2.6M181 101v2.5h-2.6"/>
<path d="M184.1 101v1.2M184.1 107.3v1.3M52.7 129.5h-4.4v48.9M57.8 129.5h3.8M61.6 134.6h-25.4v9.5h-1.9M76.8 129.5h14.6M76.8 134.6h2.6v26.7M92.7 137.8h-4.4v3.8M92.7 125.7h-4.4v3.8M97.8 137.8h20.9M97.8 125.7h20.9v24.2h-20.9M142.9 137.8h-2.6v34.3h36.9"/>
<path d="M155.6 137.8h27.3M174 132.7h-8.3v33M179.1 132.7h3.8M198.1 132.7h14.6M198.1 137.8h2.6v14.6M214 128.9h-4.5v3.8M219.1 128.9h20.9v12.1h-20.9M19 146.7h2.6M19 149.2h2.6M21.6 144.1h-2.6v40.7h40.1M34.3 146.7h27.3M34.3 149.2h1.9v9.6h25.4"/>
<path d="M48.3 141.6h4.4M48.3 153.7h4.4M57.8 141.6h3.8M57.8 153.7h3.8M76.8 141.6h14.6M76.8 153.7h14.6M76.8 146.7h2.6M76.8 158.8h2.6M92.7 149.9h-4.4v3.8M140.3 140.3h2.6M155.6 140.3h1.9v9.6h25.4M165.7 144.8h8.3"/>
<path d="M179.1 144.8h3.8M198.1 144.8h14.6M198.1 149.9h2.6M214 141h-4.5v3.8M48.3 177.2h10.8M81.9 177.2v2.5h-2.5M85.1 177.2v1.2M93.3 175.3v1.9h-13.9M165.7 170.8v1.3M165.7 164.5h11.5M177.2 169.5h-2.6v2.6M197.5 172.1h14v2.5"/>
<path d="M197.5 169.5h2.5v2.6M200 164.5v2.5h-2.5M203.2 164.5v1.2M203.2 170.8v1.3M211.5 162.6v1.9h-14M48.3 183.5v1.3M59.1 182.2h-2.6v2.6M79.4 182.2h2.5v2.6M79.4 184.8h13.9v2.5M85.1 183.5v1.3"/>
</g>
<g fill="#009600" stroke="#009600" stroke-width=".18">
<circle cx="181" cy="101" r=".46"/>
<circle cx="155.6" cy="108.6" r=".46"/>
<circle cx="147.3" cy="108.6" r=".46"/>
<circle cx="147.3" cy="101" r=".46"/>
<circle cx="184.1" cy="108.6" r=".46"/>
<circle cx="181" cy="108.6" r=".46"/>
<circle cx="184.1" cy="101" r=".46"/>
<circle cx="140.3" cy="140.3" r=".46"/>
<circle cx="212.7" cy="37.5" r=".46"/>
<circle cx="212.7" cy="49.5" r=".46"/>
<circle cx="187.3" cy="41.3" r=".46"/>
<circle cx="212.7" cy="25.4" r=".46"/>
<circle cx="187.3" cy="29.2" r=".46"/>
<circle cx="147.3" cy="77.5" r=".46"/>
<circle cx="187.3" cy="77.5" r=".46"/>
<circle cx="178.4" cy="82.6" r=".46"/>
<circle cx="147.3" cy="65.4" r=".46"/>
<circle cx="203.2" cy="172.1" r=".46"/>
<circle cx="200" cy="172.1" r=".46"/>
<circle cx="165.7" cy="164.5" r=".46"/>
<circle cx="165.7" cy="172.1" r=".46"/>
<circle cx="165.7" cy="144.8" r=".46"/>
<circle cx="203.2" cy="164.5" r=".46"/>
<circle cx="174.6" cy="172.1" r=".46"/>
<circle cx="200" cy="164.5" r=".46"/>
<circle cx="200.7" cy="149.9" r=".46"/>
<circle cx="209.5" cy="144.8" r=".46"/>
<circle cx="209.5" cy="132.7" r=".46"/>
<circle cx="147.3" cy="41.3" r=".46"/>
<circle cx="147.3" cy="53.3" r=".46"/>
<circle cx="187.3" cy="65.4" r=".46"/>
<circle cx="187.3" cy="53.3" r=".46"/>
<circle cx="178.4" cy="58.4" r=".46"/>
<circle cx="178.4" cy="70.5" r=".46"/>
<circle cx="178.4" cy="46.4" r=".46"/>
<circle cx="212.7" cy="61.6" r=".46"/>
<circle cx="78.1" cy="101" r=".46"/>
<circle cx="81.3" cy="101" r=".46"/>
<circle cx="78.1" cy="108.6" r=".46"/>
<circle cx="81.3" cy="108.6" r=".46"/>
<circle cx="75.6" cy="82.6" r=".46"/>
<circle cx="84.5" cy="77.5" r=".46"/>
<circle cx="81.9" cy="184.8" r=".46"/>
<circle cx="79.4" cy="146.7" r=".46"/>
<circle cx="79.4" cy="158.8" r=".46"/>
<circle cx="56.5" cy="184.8" r=".46"/>
<circle cx="48.3" cy="184.8" r=".46"/>
<circle cx="75.6" cy="70.5" r=".46"/>
<circle cx="75.6" cy="58.4" r=".46"/>
<circle cx="44.4" cy="41.3" r=".46"/>
<circle cx="84.5" cy="53.3" r=".46"/>
<circle cx="75.6" cy="46.4" r=".46"/>
<circle cx="44.4" cy="53.3" r=".46"/>
<circle cx="44.4" cy="65.4" r=".46"/>
<circle cx="84.5" cy="65.4" r=".46"/>
<circle cx="109.9" cy="37.5" r=".46"/>
<circle cx="109.9" cy="49.5" r=".46"/>
<circle cx="118.1" cy="58.4" r=".46"/>
<circle cx="118.1" cy="61" r=".46"/>
<circle cx="118.1" cy="63.5" r=".46"/>
<circle cx="84.5" cy="41.3" r=".46"/>
<circle cx="118.1" cy="55.9" r=".46"/>
<circle cx="109.9" cy="61.6" r=".46"/>
<circle cx="84.5" cy="29.2" r=".46"/>
<circle cx="109.9" cy="25.4" r=".46"/>
<circle cx="44.4" cy="77.5" r=".46"/>
<circle cx="15.2" cy="63.5" r=".46"/>
<circle cx="52.7" cy="108.6" r=".46"/>
<circle cx="15.2" cy="58.4" r=".46"/>
<circle cx="15.2" cy="61" r=".46"/>
<circle cx="44.4" cy="108.6" r=".46"/>
<circle cx="44.4" cy="101" r=".46"/>
<circle cx="15.2" cy="55.9" r=".46"/>
<circle cx="88.3" cy="129.5" r=".46"/>
<circle cx="88.3" cy="141.6" r=".46"/>
<circle cx="85.1" cy="177.2" r=".46"/>
<circle cx="81.9" cy="177.2" r=".46"/>
<circle cx="118.7" cy="137.8" r=".46"/>
<circle cx="88.3" cy="153.7" r=".46"/>
<circle cx="85.1" cy="184.8" r=".46"/>
<circle cx="19" cy="149.2" r=".46"/>
<circle cx="19" cy="146.7" r=".46"/>
<circle cx="48.3" cy="177.2" r=".46"/>
<circle cx="48.3" cy="141.6" r=".46"/>
<circle cx="48.3" cy="153.7" r=".46"/>
</g>
<use href="#words"/>
</svg>
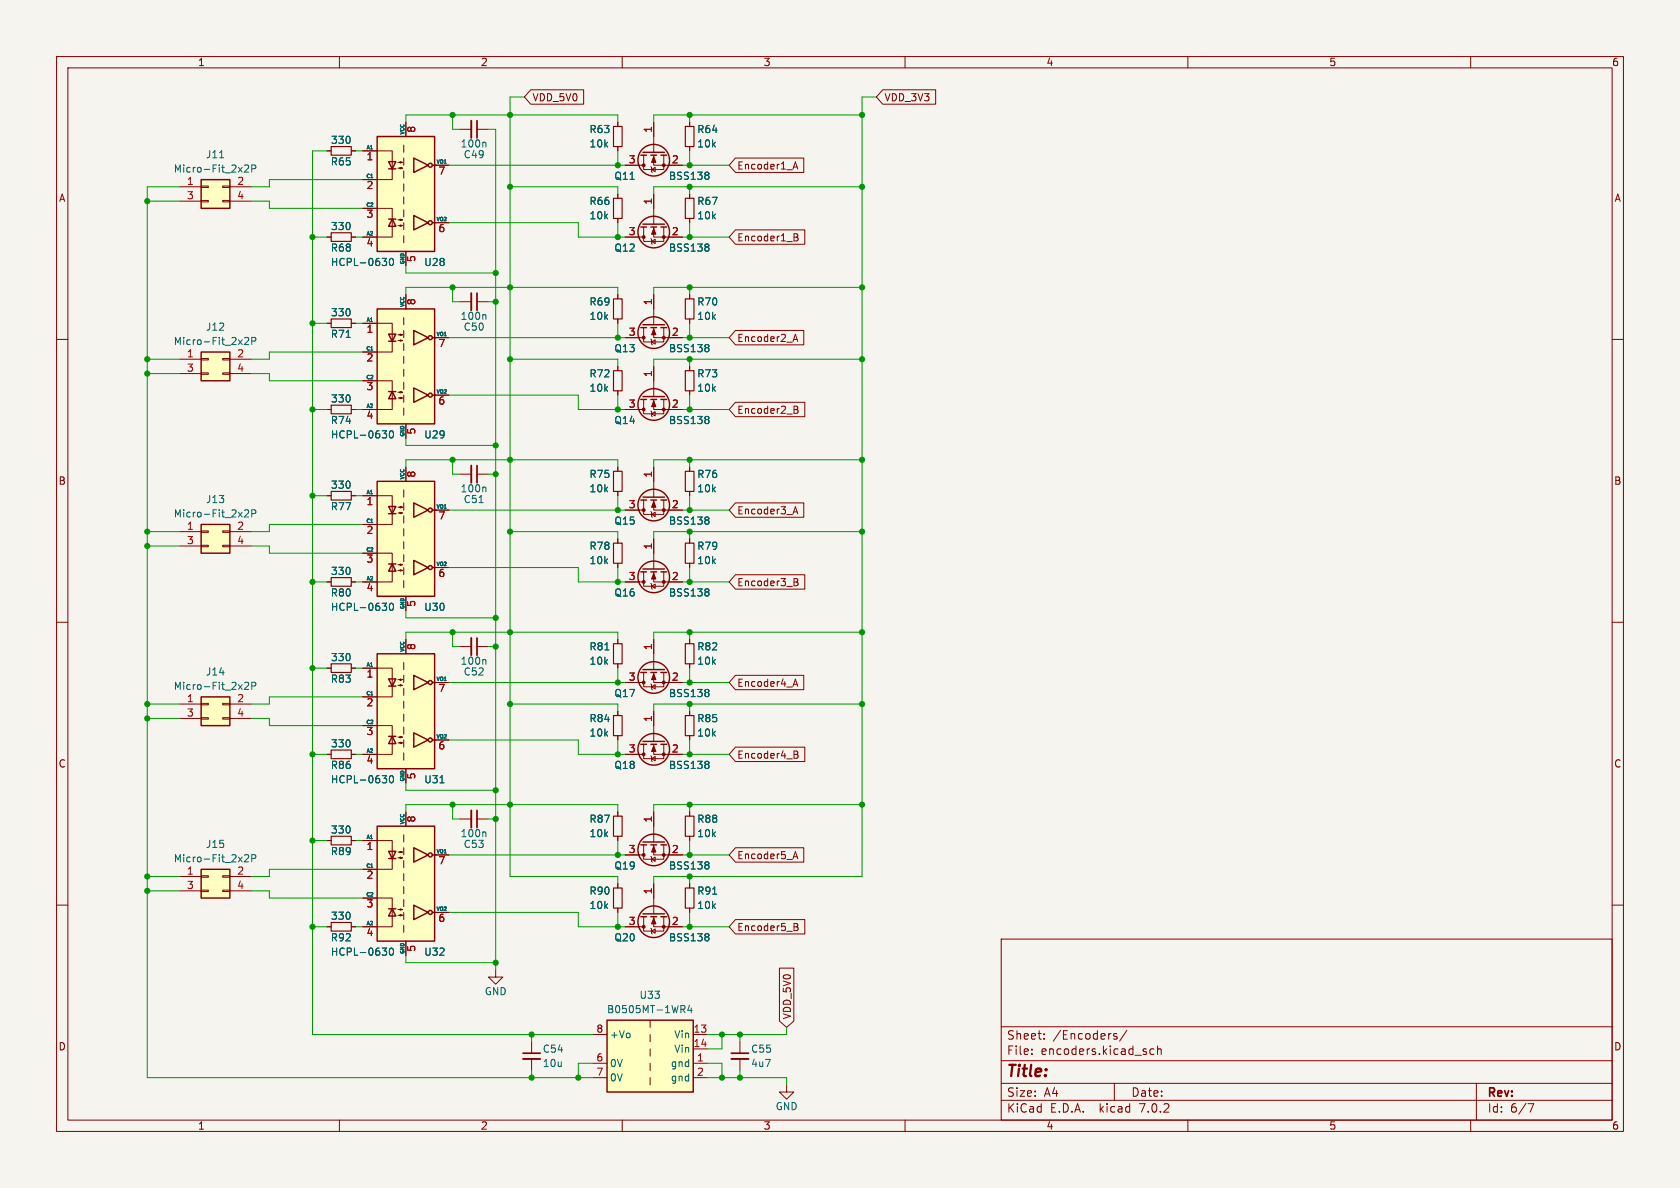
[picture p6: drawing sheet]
<svg xmlns="http://www.w3.org/2000/svg" width="297mm" height="210mm" viewBox="0 0 297 210" stroke-linecap="round" stroke-linejoin="round" font-family="sans-serif">
<defs><g id="words">
<text font-size="2.8" fill="#840000" x="178" y="190.8">Title:</text>
<g font-size="2.1" fill="#840000">
<text x="178" y="183.9">Sheet:</text>
<text x="186.2" y="183.9">/Encoders/</text>
<text x="178" y="186.6">File:</text>
<text x="184" y="186.6">encoders.kicad_sch</text>
<text x="178" y="196.8">KiCad</text>
<text x="178" y="194">Size:</text>
<text x="184.6" y="194">A4</text>
<text x="185.7" y="196.8">E.D.A.</text>
<text x="194.4" y="196.8">kicad</text>
<text x="200" y="194">Date:</text>
<text x="201.5" y="196.8">7.0.2</text>
<text x="263" y="194.2">Rev:</text>
<text x="263" y="196.8">Id:</text>
<text x="267" y="196.8">6/7</text>
</g>
<g font-size="1.8" fill="#840000">
<text x="35" y="11.8">1</text>
<text x="85" y="11.8">2</text>
<text x="135" y="11.8">3</text>
<text x="185" y="11.8">4</text>
<text x="235" y="11.8">5</text>
<text x="285" y="11.8">6</text>
<text x="94.1" y="18.1">VDD_5V0</text>
<text x="156.4" y="18.1">VDD_3V3</text>
<text x="10.4" y="35.8">A</text>
<text x="130.3" y="30.1">Encoder1_A</text>
<text x="285.4" y="35.8">A</text>
<text x="130.3" y="42.8">Encoder1_B</text>
<text x="130.3" y="60.6">Encoder2_A</text>
<text x="130.3" y="73.3">Encoder2_B</text>
<text x="10.3" y="85.8">B</text>
<text x="285.3" y="85.8">B</text>
<text x="130.3" y="91.1">Encoder3_A</text>
<text x="130.3" y="103.8">Encoder3_B</text>
<text x="130.3" y="121.6">Encoder4_A</text>
<text x="10.3" y="135.8">C</text>
<text x="130.3" y="134.3">Encoder4_B</text>
<text x="285.3" y="135.8">C</text>
<text x="130.3" y="152">Encoder5_A</text>
<text x="130.3" y="164.7">Encoder5_B</text>
<text x="10.3" y="185.8">D</text>
<text x="140" y="180.2" transform="rotate(-90 140 180.2)">VDD_5V0</text>
<text x="285.3" y="185.8">D</text>
<text x="35" y="199.8">1</text>
<text x="85" y="199.8">2</text>
<text x="135" y="199.8">3</text>
<text x="185" y="199.8">4</text>
<text x="235" y="199.8">5</text>
<text x="285" y="199.8">6</text>
</g>
<g font-size="1.8" fill="#a90000">
<text x="73.7" y="23.5" transform="rotate(-90 73.7 23.5)">8</text>
<text x="115.3" y="23.5" transform="rotate(-90 115.3 23.5)">1</text>
<text x="64.7" y="28.6">1</text>
<text x="111.1" y="29">3</text>
<text x="118.7" y="29">2</text>
<text x="33" y="32.8">1</text>
<text x="33" y="35.3">3</text>
<text x="41.9" y="32.8">2</text>
<text x="41.9" y="35.3">4</text>
<text x="64.7" y="33.7">2</text>
<text x="77.4" y="31.1">7</text>
<text x="64.7" y="38.7">3</text>
<text x="77.4" y="41.3">6</text>
<text x="111.1" y="41.7">3</text>
<text x="115.3" y="36.2" transform="rotate(-90 115.3 36.2)">1</text>
<text x="118.7" y="41.7">2</text>
<text x="64.7" y="43.8">4</text>
<text x="73.7" y="46.4" transform="rotate(-90 73.7 46.4)">5</text>
<text x="64.7" y="59.1">1</text>
<text x="73.7" y="54" transform="rotate(-90 73.7 54)">8</text>
<text x="111.1" y="59.4">3</text>
<text x="115.3" y="54" transform="rotate(-90 115.3 54)">1</text>
<text x="118.7" y="59.4">2</text>
<text x="33" y="63.2">1</text>
<text x="33" y="65.8">3</text>
<text x="41.9" y="63.2">2</text>
<text x="41.9" y="65.8">4</text>
<text x="64.7" y="64.1">2</text>
<text x="77.4" y="61.6">7</text>
<text x="64.7" y="69.2">3</text>
<text x="77.4" y="71.8">6</text>
<text x="115.3" y="66.7" transform="rotate(-90 115.3 66.7)">1</text>
<text x="64.7" y="74.3">4</text>
<text x="73.7" y="76.9" transform="rotate(-90 73.7 76.9)">5</text>
<text x="111.1" y="72.1">3</text>
<text x="118.7" y="72.1">2</text>
<text x="64.7" y="89.5">1</text>
<text x="73.7" y="84.5" transform="rotate(-90 73.7 84.5)">8</text>
<text x="111.1" y="89.9">3</text>
<text x="115.3" y="84.5" transform="rotate(-90 115.3 84.5)">1</text>
<text x="118.7" y="89.9">2</text>
<text x="33" y="93.7">1</text>
<text x="41.9" y="93.7">2</text>
<text x="64.7" y="94.6">2</text>
<text x="77.4" y="92.1">7</text>
<text x="33" y="96.3">3</text>
<text x="41.9" y="96.3">4</text>
<text x="64.7" y="99.7">3</text>
<text x="115.3" y="97.2" transform="rotate(-90 115.3 97.2)">1</text>
<text x="64.7" y="104.8">4</text>
<text x="73.7" y="107.3" transform="rotate(-90 73.7 107.3)">5</text>
<text x="77.4" y="102.2">6</text>
<text x="111.1" y="102.6">3</text>
<text x="118.7" y="102.6">2</text>
<text x="73.7" y="115" transform="rotate(-90 73.7 115)">8</text>
<text x="115.3" y="115" transform="rotate(-90 115.3 115)">1</text>
<text x="33" y="124.2">1</text>
<text x="41.9" y="124.2">2</text>
<text x="64.7" y="120">1</text>
<text x="64.7" y="125.1">2</text>
<text x="77.4" y="122.6">7</text>
<text x="111.1" y="120.4">3</text>
<text x="118.7" y="120.4">2</text>
<text x="33" y="126.7">3</text>
<text x="41.9" y="126.7">4</text>
<text x="64.7" y="130.2">3</text>
<text x="115.3" y="127.7" transform="rotate(-90 115.3 127.7)">1</text>
<text x="64.7" y="135.3">4</text>
<text x="73.7" y="137.8" transform="rotate(-90 73.7 137.8)">5</text>
<text x="77.4" y="132.7">6</text>
<text x="111.1" y="133.1">3</text>
<text x="118.7" y="133.1">2</text>
<text x="73.7" y="145.4" transform="rotate(-90 73.7 145.4)">8</text>
<text x="115.3" y="145.4" transform="rotate(-90 115.3 145.4)">1</text>
<text x="33" y="154.7">1</text>
<text x="41.9" y="154.7">2</text>
<text x="64.7" y="150.5">1</text>
<text x="64.7" y="155.6">2</text>
<text x="77.4" y="153">7</text>
<text x="111.1" y="150.9">3</text>
<text x="118.7" y="150.9">2</text>
<text x="33" y="157.2">3</text>
<text x="41.9" y="157.2">4</text>
<text x="64.7" y="160.7">3</text>
<text x="115.3" y="158.1" transform="rotate(-90 115.3 158.1)">1</text>
<text x="64.7" y="165.7">4</text>
<text x="77.4" y="163.2">6</text>
<text x="111.1" y="163.6">3</text>
<text x="118.7" y="163.6">2</text>
<text x="73.7" y="168.3" transform="rotate(-90 73.7 168.3)">5</text>
<text x="105.4" y="182.6">8</text>
<text x="122.6" y="182.6">13</text>
<text x="122.6" y="185.2">14</text>
<text x="105.4" y="187.7">6</text>
<text x="105.4" y="190.2">7</text>
<text x="123.2" y="187.7">1</text>
<text x="123.2" y="190.2">2</text>
</g>
<g font-size="1.8" fill="#006464">
<text x="104.1" y="23.7">R63</text>
<text x="123.2" y="23.7">R64</text>
<text x="36.3" y="28.1">J11</text>
<text x="58.4" y="29.4">R65</text>
<text x="58.4" y="25.6">330</text>
<text x="81.4" y="26.2">100n</text>
<text x="81.9" y="28.1">C49</text>
<text x="104.1" y="26.2">10k</text>
<text x="123.2" y="26.2">10k</text>
<text x="30.7" y="30.7">Micro-Fit_2x2P</text>
<text x="108.6" y="31.9">Q11</text>
<text x="118.2" y="31.9">BSS138</text>
<text x="58.4" y="40.8">330</text>
<text x="104.1" y="36.4">R66</text>
<text x="104.1" y="38.9">10k</text>
<text x="123.2" y="36.4">R67</text>
<text x="123.2" y="38.9">10k</text>
<text x="58.4" y="44.6">R68</text>
<text x="58.4" y="47.2">HCPL-0630</text>
<text x="74.9" y="47.2">U28</text>
<text x="108.6" y="44.6">Q12</text>
<text x="118.2" y="44.6">BSS138</text>
<text x="36.3" y="58.6">J12</text>
<text x="58.4" y="59.9">R71</text>
<text x="58.4" y="56.1">330</text>
<text x="81.4" y="56.7">100n</text>
<text x="81.9" y="58.6">C50</text>
<text x="104.1" y="54.2">R69</text>
<text x="104.1" y="56.7">10k</text>
<text x="123.2" y="54.2">R70</text>
<text x="123.2" y="56.7">10k</text>
<text x="30.7" y="61.2">Micro-Fit_2x2P</text>
<text x="108.6" y="62.4">Q13</text>
<text x="118.2" y="62.4">BSS138</text>
<text x="58.4" y="71.3">330</text>
<text x="104.1" y="66.9">R72</text>
<text x="104.1" y="69.4">10k</text>
<text x="123.2" y="66.9">R73</text>
<text x="123.2" y="69.4">10k</text>
<text x="58.4" y="75.1">R74</text>
<text x="58.4" y="77.7">HCPL-0630</text>
<text x="74.9" y="77.7">U29</text>
<text x="108.6" y="75.1">Q14</text>
<text x="118.2" y="75.1">BSS138</text>
<text x="36.3" y="89.1">J13</text>
<text x="58.4" y="86.6">330</text>
<text x="81.4" y="87.2">100n</text>
<text x="81.9" y="89.1">C51</text>
<text x="104.1" y="84.6">R75</text>
<text x="104.1" y="87.2">10k</text>
<text x="123.2" y="84.6">R76</text>
<text x="123.2" y="87.2">10k</text>
<text x="30.7" y="91.6">Micro-Fit_2x2P</text>
<text x="58.4" y="90.4">R77</text>
<text x="108.6" y="92.9">Q15</text>
<text x="118.2" y="92.9">BSS138</text>
<text x="58.4" y="101.8">330</text>
<text x="104.1" y="97.3">R78</text>
<text x="104.1" y="99.9">10k</text>
<text x="123.2" y="97.3">R79</text>
<text x="123.2" y="99.9">10k</text>
<text x="58.4" y="105.6">R80</text>
<text x="108.6" y="105.6">Q16</text>
<text x="118.2" y="105.6">BSS138</text>
<text x="58.4" y="108.1">HCPL-0630</text>
<text x="74.9" y="108.1">U30</text>
<text x="36.3" y="119.6">J14</text>
<text x="58.4" y="117">330</text>
<text x="81.4" y="117.7">100n</text>
<text x="81.9" y="119.6">C52</text>
<text x="104.1" y="115.1">R81</text>
<text x="104.1" y="117.7">10k</text>
<text x="123.2" y="115.1">R82</text>
<text x="123.2" y="117.7">10k</text>
<text x="30.7" y="122.1">Micro-Fit_2x2P</text>
<text x="58.4" y="120.8">R83</text>
<text x="108.6" y="123.4">Q17</text>
<text x="118.2" y="123.4">BSS138</text>
<text x="104.1" y="127.8">R84</text>
<text x="104.1" y="130.4">10k</text>
<text x="123.2" y="127.8">R85</text>
<text x="123.2" y="130.4">10k</text>
<text x="58.4" y="136.1">R86</text>
<text x="58.4" y="132.3">330</text>
<text x="108.6" y="136.1">Q18</text>
<text x="118.2" y="136.1">BSS138</text>
<text x="58.4" y="138.6">HCPL-0630</text>
<text x="74.9" y="138.6">U31</text>
<text x="58.4" y="147.5">330</text>
<text x="81.4" y="148.1">100n</text>
<text x="104.1" y="145.6">R87</text>
<text x="104.1" y="148.1">10k</text>
<text x="123.2" y="145.6">R88</text>
<text x="123.2" y="148.1">10k</text>
<text x="30.7" y="152.6">Micro-Fit_2x2P</text>
<text x="36.3" y="150.1">J15</text>
<text x="58.4" y="151.3">R89</text>
<text x="81.9" y="150.1">C53</text>
<text x="108.6" y="153.9">Q19</text>
<text x="118.2" y="153.9">BSS138</text>
<text x="104.1" y="158.3">R90</text>
<text x="104.1" y="160.8">10k</text>
<text x="123.2" y="158.3">R91</text>
<text x="123.2" y="160.8">10k</text>
<text x="58.4" y="166.6">R92</text>
<text x="58.4" y="162.8">330</text>
<text x="108.6" y="166.6">Q20</text>
<text x="118.2" y="166.6">BSS138</text>
<text x="58.4" y="169.1">HCPL-0630</text>
<text x="74.9" y="169.1">U32</text>
<text x="85.6" y="176.1">GND</text>
<text x="107.3" y="179.3">B0505MT-1WR4</text>
<text x="113" y="176.7">U33</text>
<text x="107.8" y="183.7">+Vo</text>
<text x="119.1" y="183.7">Vin</text>
<text x="95.9" y="186.2">C54</text>
<text x="95.9" y="188.8">10u</text>
<text x="107.8" y="188.8">0V</text>
<text x="107.8" y="191.3">0V</text>
<text x="118.5" y="188.8">gnd</text>
<text x="118.5" y="191.3">gnd</text>
<text x="119.1" y="186.2">Vin</text>
<text x="132.7" y="186.2">C55</text>
<text x="132.7" y="188.8">4u7</text>
<text x="137.1" y="196.4">GND</text>
</g>
<g font-size=".9" fill="#006464">
<text x="71.5" y="23.9" transform="rotate(-90 71.5 23.9)">VCC</text>
<text x="64.7" y="26.4">A1</text>
<text x="77.1" y="29">VO1</text>
<text x="64.7" y="31.5">C1</text>
<text x="64.7" y="36.6">C2</text>
<text x="64.7" y="41.7">A2</text>
<text x="77.1" y="39.1">VO2</text>
<text x="71.5" y="46.8" transform="rotate(-90 71.5 46.8)">GND</text>
<text x="64.7" y="56.9">A1</text>
<text x="71.5" y="54.3" transform="rotate(-90 71.5 54.3)">VCC</text>
<text x="77.1" y="59.4">VO1</text>
<text x="64.7" y="62">C1</text>
<text x="64.7" y="67.1">C2</text>
<text x="77.1" y="69.6">VO2</text>
<text x="64.7" y="72.1">A2</text>
<text x="71.5" y="77.3" transform="rotate(-90 71.5 77.3)">GND</text>
<text x="64.7" y="87.4">A1</text>
<text x="71.5" y="84.8" transform="rotate(-90 71.5 84.8)">VCC</text>
<text x="77.1" y="89.9">VO1</text>
<text x="64.7" y="92.5">C1</text>
<text x="64.7" y="97.5">C2</text>
<text x="77.1" y="100.1">VO2</text>
<text x="64.7" y="102.6">A2</text>
<text x="71.5" y="107.7" transform="rotate(-90 71.5 107.7)">GND</text>
<text x="64.7" y="117.9">A1</text>
<text x="71.5" y="115.3" transform="rotate(-90 71.5 115.3)">VCC</text>
<text x="64.7" y="122.9">C1</text>
<text x="77.1" y="120.4">VO1</text>
<text x="64.7" y="128">C2</text>
<text x="77.1" y="130.6">VO2</text>
<text x="64.7" y="133.1">A2</text>
<text x="71.5" y="138.2" transform="rotate(-90 71.5 138.2)">GND</text>
<text x="64.7" y="148.3">A1</text>
<text x="71.5" y="145.8" transform="rotate(-90 71.5 145.8)">VCC</text>
<text x="64.7" y="153.4">C1</text>
<text x="77.1" y="150.9">VO1</text>
<text x="64.7" y="158.5">C2</text>
<text x="77.1" y="161">VO2</text>
<text x="64.7" y="163.6">A2</text>
<text x="71.5" y="168.7" transform="rotate(-90 71.5 168.7)">GND</text>
</g>
</g></defs>
<path d="M0 0h297v210h-297z" fill="#f5f4ef" stroke="#f5f4ef" stroke-width=".18"/>
<g fill="none" stroke="#840000" stroke-width=".18">
<path d="M10 10h277v190h-277zM12 12h273v186h-273zM60 10v2M93.8 15.9h9.4v2.5h-9.4l-1.1-1.3zM110 10v2M156.1 15.9h9.3v2.5h-9.3l-1.2-1.3zM160 10v2M210 10v2M260 10v2M31.7 33h3.9M31.7 35.6h3.9M35.6 35.4h1.2v.3h-1.2z"/>
<path d="M35.6 32.9h1.2v.2h-1.2zM39.4 35.4h1.2v.3h-1.2zM39.4 32.9h1.2v.2h-1.2zM40.6 33h3.8M40.6 35.6h3.8M57.8 26.7h.7M62.1 26.7h.8M64.1 26.7h2.6M64.1 31.8h2.6M64.1 36.8h2.6M66.8 26.7h2.5v3.3M66.8 36.8h2.5v3.3"/>
<path d="M69.3 29.8v2h-2.5M70.4 39.9h.7l-.4 .1v-.2l.4 .1M70.4 38.9h.7l-.4 .1v-.3l.4 .2M70.4 29.7h.7l-.4 .1v-.2l.4 .1M70.4 28.7h.7l-.4 .1v-.2l.4 .1M71.4 25.7v1.2M71.4 27.9v1.3M71.4 30.2v1.3M71.4 32.5v1.3M71.4 34.8v1.3M71.4 37.1v1.3M71.4 39.4v1.2"/>
<path d="M71.8 21.6v2.5M76.8 29.2h2.6M76.8 39.4h2.6M81.3 22.9h2M84.3 22.9h2.1M109.2 21.6v.8M109.2 25.9v.8M109.2 34.3v.8M109.2 38.6v.8M110.5 29.2h3.3M113.8 27.4v2.6h3.5v-2.6M115.1 29.5l.1 .1v.8l.1 .1"/>
<path d="M115.2 30l.6-.4v.8zM115.6 27.4v1.8h5M115.6 21.6v5.3M115.6 34.3v5.3M121.9 21.6v.8M121.9 25.9v.8M121.9 34.3v.8M121.9 38.6v.8M130 27.9h12.1v2.6h-12.1l-1.1-1.3zM140.3 29.5h.6M140.6 28.6l.4 1.3M10 60h2"/>
<path d="M57.8 57.2h.7M57.8 41.9h.7M62.1 57.2h.8M62.1 41.9h.8M64.1 57.2h2.6M64.1 41.9h2.6M66.8 57.2h2.5v3.3M69.3 40v1.9h-2.5M70.4 59.2h.7l-.4 .1v-.2l.4 .1M71.4 41.7v1.2M71.4 56.1v1.3M71.4 58.4v1.3"/>
<path d="M71.8 44.5v2.5M71.8 52.1v2.5M76.8 59.7h2.6M81.3 53.3h2M84.3 53.3h2.1M109.2 52.1v.7M109.2 56.4v.8M110.5 59.7h3.3M110.5 41.9h3.3M113.8 57.9v2.6h3.5v-2.6M113.8 40.1v2.6h3.5v-2.6M115.1 59.9l.1 .2v.7l.1 .2"/>
<path d="M115.1 42.2l.1 .1v.8l.1 .1M115.2 42.7l.6-.4v.8zM115.6 57.9v1.8h5M115.6 40.1v1.8h5M115.6 52.1v5.3M121.9 52.1v.7M121.9 56.4v.8M130 58.4h12.1v2.6h-12.1l-1.1-1.3zM130 40.6h12.3v2.6h-12.3l-1.1-1.3zM140.4 41.3l.6 .1v.3l-.2 .2M140.4 41.9h.4M140.6 59.1l.4 1.3"/>
<path d="M140.8 41.9l.3 .3-.1 .3-.6 .1M285 60h2M31.7 63.5h3.9M31.7 66h3.9M35.6 65.9h1.2v.3h-1.2zM35.6 63.4h1.2v.2h-1.2zM39.4 65.9h1.2v.3h-1.2zM39.4 63.4h1.2v.2h-1.2zM40.6 63.5h3.8M40.6 66h3.8M57.8 72.4h.7M62.1 72.4h.8"/>
<path d="M64.1 72.4h2.6M64.1 62.2h2.6M64.1 67.3h2.6M66.8 67.3h2.5v3.3M69.3 70.5v1.9h-2.5M69.3 60.3v1.9h-2.5M70.4 70.4h.7l-.4 .1v-.3l.4 .2M70.4 69.3h.7l-.4 .2v-.3l.4 .1M70.4 60.2h.7l-.4 .1v-.2l.4 .1M71.4 60.7v1.3M71.4 63v1.3M71.4 65.3v1.2"/>
<path d="M71.4 67.6v1.2M71.4 69.9v1.2M71.4 72.1v1.3M71.8 74.9v2.6M76.8 69.9h2.6M109.2 64.8v.7M109.2 69.1v.8M110.5 72.4h3.3M113.8 70.6v2.6h3.5v-2.6M115.1 72.6l.1 .2v.7l.1 .2M115.2 60.5l.6-.4v.7zM115.2 73.2l.6-.4v.7z"/>
<path d="M115.6 70.6v1.8h5M115.6 64.8v5.3M121.9 64.8v.7M121.9 69.1v.8M130 71.1h12.3v2.6h-12.3l-1.1-1.3zM140.3 60h.6M140.4 72.4h.4M140.4 71.8l.6 .1v.3l-.2 .2M140.8 72.4l.3 .2-.1 .3-.6 .2M31.7 94h3.9M31.7 96.5h3.9M35.6 96.4h1.2v.2h-1.2z"/>
<path d="M35.6 93.9h1.2v.2h-1.2zM39.4 96.4h1.2v.2h-1.2zM39.4 93.9h1.2v.2h-1.2zM40.6 94h3.8M40.6 96.5h3.8M57.8 87.6h.7M62.1 87.6h.8M64.1 87.6h2.6M64.1 92.7h2.6M64.1 97.8h2.6M66.8 87.6h2.5v3.3M66.8 97.8h2.5v3.3"/>
<path d="M69.3 90.8v1.9h-2.5M70.4 99.8h.7l-.4 .1v-.2l.4 .1M70.4 90.7h.7l-.4 .1v-.2l.4 .1M70.4 89.7h.7l-.4 .1v-.3l.4 .2M71.4 86.6v1.3M71.4 88.9v1.3M71.4 91.2v1.3M71.4 93.5v1.2M71.4 95.8v1.2M71.4 98v1.3M71.8 82.6v2.5M76.8 90.2h2.6"/>
<path d="M81.3 83.8h2M84.3 83.8h2.1M109.2 82.6v.7M109.2 86.9v.7M109.2 95.3v.7M109.2 99.6v.7M110.5 90.2h3.3M113.8 88.4v2.5h3.5v-2.5M115.1 90.4l.1 .2v.7l.1 .1M115.2 90.9l.6-.3v.7zM115.6 88.4v1.8h5M115.6 82.6v5.3"/>
<path d="M115.6 95.3v5.3M121.9 82.6v.7M121.9 86.9v.7M121.9 95.3v.7M121.9 99.6v.7M130 88.9h12.1v2.5h-12.1l-1.1-1.2zM140.3 90.5h.6M140.6 89.6l.4 1.2M10 110h2M57.8 102.9h.7M57.8 118.1h.7M62.1 102.9h.8"/>
<path d="M62.1 118.1h.8M64.1 102.9h2.6M64.1 118.1h2.6M66.8 118.1h2.5v3.3M69.3 101v1.9h-2.5M70.4 100.8h.7l-.4 .2v-.3l.4 .1M71.4 100.3v1.3M71.4 102.6v1.3M71.4 117.1v1.3M71.4 119.4v1.3M71.8 105.4v2.6M71.8 113v2.6"/>
<path d="M76.8 100.3h2.6M81.3 114.3h2M84.3 114.3h2.1M109.2 113v.8M109.2 117.3v.8M110.5 102.9h3.3M113.8 118.9v2.5h3.5v-2.5M113.8 101.1v2.5h3.5v-2.5M115.1 103.1l.1 .2v.7l.1 .1M115.2 103.6l.6-.3v.7zM115.6 118.9v1.8h5M115.6 101.1v1.8h5"/>
<path d="M115.6 113v5.4M121.9 113v.8M121.9 117.3v.8M130 119.4h12.1v2.5h-12.1l-1.1-1.2zM130 101.6h12.3v2.5h-12.3l-1.1-1.2zM140.4 102.9h.4M140.4 102.3l.6 .1v.2l-.2 .3M140.8 102.9l.3 .2-.1 .3-.6 .1M285 110h2M31.7 124.5h3.9M31.7 127h3.9M35.6 126.9h1.2v.2h-1.2z"/>
<path d="M35.6 124.3h1.2v.3h-1.2zM39.4 126.9h1.2v.2h-1.2zM39.4 124.3h1.2v.3h-1.2zM40.6 124.5h3.8M40.6 127h3.8M57.8 133.4h.7M62.1 133.4h.8M64.1 123.2h2.6M64.1 128.3h2.6M64.1 133.4h2.6M66.8 128.3h2.5v3.3M69.3 131.4v2h-2.5"/>
<path d="M69.3 121.3v1.9h-2.5M70.4 131.3h.7l-.4 .1v-.2l.4 .1M70.4 130.3h.7l-.4 .1v-.2l.4 .1M70.4 121.2h.7l-.4 .1v-.3l.4 .2M70.4 120.1h.7l-.4 .2v-.3l.4 .1M71.4 121.7v1.2M71.4 124v1.2M71.4 126.2v1.3M71.4 128.5v1.3M71.4 130.8v1.3M71.4 133.1v1.3M71.8 135.9v2.5"/>
<path d="M76.8 130.8h2.6M76.8 120.7h2.6M109.2 125.7v.8M109.2 130v.8M110.5 133.4h3.3M110.5 120.7h3.3M113.8 131.6v2.5h3.5v-2.5M115.1 120.9l.1 .1v.8l.1 .1M115.1 133.6l.1 .1v.8l.1 .1M115.2 121.4l.6-.4v.8zM115.2 134.1l.6-.4v.8zM115.6 131.6v1.8h5"/>
<path d="M115.6 125.7v5.4M121.9 125.7v.8M121.9 130v.8M130 132.1h12.3v2.5h-12.3l-1.1-1.2zM140.3 121h.6M140.4 133.4h.4M140.4 132.8l.6 .1v.2l-.2 .3M140.6 120.1l.4 1.2M140.8 133.4l.3 .2-.1 .3-.6 .1M10 160h2M31.7 154.9h3.9M31.7 157.5h3.9"/>
<path d="M35.6 157.4h1.2v.2h-1.2zM35.6 154.8h1.2v.3h-1.2zM39.4 157.4h1.2v.2h-1.2zM39.4 154.8h1.2v.3h-1.2zM40.6 154.9h3.8M40.6 157.5h3.8M57.8 148.6h.7M62.1 148.6h.8M64.1 148.6h2.6M64.1 153.7h2.6M64.1 158.8h2.6M66.8 148.6h2.5v3.3"/>
<path d="M66.8 158.8h2.5v3.3M69.3 151.8v1.9h-2.5M70.4 151.6h.7l-.4 .2v-.3l.4 .1M70.4 150.6h.7l-.4 .1v-.2l.4 .1M71.4 147.6v1.2M71.4 149.9v1.2M71.4 152.1v1.3M71.4 154.4v1.3M71.4 156.7v1.3M71.4 159v1.3M71.8 143.5v2.6M76.8 151.1h2.6"/>
<path d="M81.3 144.8h2M84.3 144.8h2.1M109.2 143.5v.8M109.2 147.8v.8M109.2 156.2v.8M110.5 151.1h3.3M113.8 149.4v2.5h3.5v-2.5M115.1 151.4l.1 .1v.8l.1 .1M115.2 151.9l.6-.4v.8zM115.6 149.4v1.7h5M115.6 143.5v5.3M115.6 156.2v5.3"/>
<path d="M121.9 143.5v.8M121.9 147.8v.8M121.9 156.2v.8M130 149.9h12.1v2.5h-12.1l-1.1-1.3zM140.3 151.4h.6M140.6 150.5l.4 1.3M285 160h2M57.8 163.8h.7M62.1 163.8h.8M64.1 163.8h2.6M69.3 161.9v1.9h-2.5M70.4 161.8h.7l-.4 .1v-.2l.4 .1"/>
<path d="M70.4 160.8h.7l-.4 .1v-.2l.4 .1M71.4 161.3v1.3M71.4 163.6v1.2M71.8 166.4v2.5M76.8 161.3h2.6M87.6 171.5v1.2h1.3l-1.3 1.3-1.2-1.3h1.2M109.2 160.5v.8M110.5 163.8h3.3M113.8 162.1v2.5h3.5v-2.5M115.1 164.1l.1 .1v.8l.1 .1M115.2 164.6l.6-.4v.8zM115.6 162.1v1.7h5"/>
<path d="M121.9 160.5v.8M130 162.6h12.3v2.5h-12.3l-1.1-1.3zM137.8 171.1h2.5v9.4l-1.2 1.1-1.3-1.1zM140.4 163.8h.4M140.4 163.2l.6 .2v.2l-.2 .2M140.8 163.8l.3 .3-.1 .3-.6 .1M177 166h108v32h-108zM60 198v2M94 184.2v2M94 187.2v2M104.8 188h2.5M104.8 182.9h2.5"/>
<path d="M104.8 190.5h2.5M110 198v2M114.9 180.3v1.3M114.9 182.9v1.3M114.9 185.4v1.3M114.9 188v1.2M114.9 190.5v1.3M122.6 185.4h2.5M122.6 188h2.5M122.6 182.9h2.5M122.6 190.5h2.5M130.8 184.2v2"/>
<path d="M130.8 187.2v2M139.1 191.8v1.2h1.2l-1.2 1.3-1.3-1.3h1.3M160 198v2M177 194.5h108M177 191.5h108M177 187.5h108M177 181.5h108M182.4 186.3v.1M182.4 185.5v.1M184.6 183.6v.1M184.6 182.8v.1M196.9 183l.6 .4-.2 .3-.4-.1"/>
<path d="M197 191.5v3M197.4 182.8l-.3-.1-.2 .2M199.2 182.1l-1.3 2M204 185.5l-.4-.1-.3 .3v.4l.1 .2h.6M204.6 185.5l.3-.1 .3 .1 .1 .9M204.6 184.9v1.5M210 198v2M260 198v2M261 191.5v6.5M270.1 195.1h1l-.6 1.5"/>
</g>
<path d="M83.3 21.3v3.1M83.3 51.8v3.1M83.3 82.3v3M83.3 112.8v3M83.3 143.3v3M92.5 187.2h3M129.3 187.2h3" fill="none" stroke="#840000" stroke-width=".33"/>
<path d="M84.3 21.3v3.1M84.3 51.8v3.1M84.3 82.3v3M84.3 112.8v3M84.3 143.3v3M92.5 186.2h3M129.3 186.2h3" fill="none" stroke="#840000" stroke-width=".3"/>
<g fill="none" stroke="#006464" stroke-width=".18">
<path d="M38.8 27.9h.8M43.2 29.3l.5-.1 .3 .3-.8 .9h.8M44.5 29.8h.6l.1-.2v-.3l-.7-.1v1.2M85.7 25.1l.2 .2v.7M125.2 30.5l.1 .2-.1 .2M125.2 31l.1 .2-.1 .4M43.2 59.8l.5-.2 .3 .4-.8 .9h.8M67.6 45.7h.7l-.4 .5M68.1 46.2l.2 .2v.3l-.2 .2M69 45.8l.1-.1a.68 .68 0 0 1 .5 .6 .68 .68 0 0 1-.5 .6l-.1-.1-.2-.3zM85.7 55.6l.2 .2v.7M125.2 43.2l.1 .2-.1 .2"/>
<path d="M125.2 43.7l.1 .2-.1 .4M44.5 60.3l.6-.1 .1-.1v-.3l-.7-.2v1.3M67.6 76.2h.7l-.4 .4M68.1 76.6l.2 .3v.3l-.2 .2M69 76.3l.1-.1a.68 .68 0 0 1 .5 .6 .68 .68 0 0 1-.5 .6l-.1-.1-.2-.4zM125.2 61l.1 .2-.1 .2M125.2 61.5l.1 .2-.1 .4M125.2 73.7l.1 .2-.1 .2M125.2 74.2l.1 .2-.1 .4M43.2 90.2l.5-.1 .3 .4-.8 .9h.8M44.5 90.8l.6-.1 .1-.2v-.3l-.7-.1v1.3M85.7 86.1l.2 .2v.6"/>
<path d="M125.2 91.5l.1 .1-.1 .3M125.2 92l.1 .2-.1 .4M67.6 106.6h.7l-.4 .5M68.1 107.1l.2 .3v.3l-.2 .2M69 106.8l.1-.2a.68 .68 0 0 1 .5 .7 .68 .68 0 0 1-.5 .6l-.1-.1-.2-.4zM85.7 116.6l.2 .2v.6M125.2 104.2l.1 .1-.1 .3M125.2 104.7l.1 .2-.1 .4M43.2 120.7l.5-.1 .3 .4-.8 .9h.8M44.5 121.3l.6-.1 .1-.2v-.3l-.7-.1v1.3M67.6 137.1h.7l-.4 .5M68.1 137.6l.2 .2v.3l-.2 .3"/>
<path d="M69 137.2l.1-.1a.68 .68 0 0 1 .5 .6 .68 .68 0 0 1-.5 .7l-.1-.1-.2-.4zM77.8 138.4h.7M125.2 121.9l.1 .2-.1 .3M125.2 122.5l.1 .2-.1 .4M125.2 134.6l.1 .2-.1 .3M125.2 135.2l.1 .2-.1 .4M43.2 151.2l.5-.1 .3 .3-.8 1h.8M44.5 151.7h.6l.1-.2v-.3l-.7-.1v1.3M85.7 147.1l.2 .1v.7M125.2 152.4l.1 .2-.1 .2M125.2 153l.1 .1-.1 .5M67.6 167.6h.7l-.4 .5"/>
<path d="M68.1 168.1l.2 .2v.3l-.2 .3M69 167.7l.1-.1a.68 .68 0 0 1 .5 .6 .68 .68 0 0 1-.5 .7l-.1-.2-.2-.3zM120.7 178.4l.4 .6M121 177.8l.1 .2-.1 .4M121.9 177.7l-.3 .9h.8M122.2 178.2v.8M125.2 165.1l.1 .2-.1 .2M125.2 165.7l.1 .1-.1 .5"/>
</g>
<g fill="none" stroke="#840000" stroke-width=".2">
<path d="M58.5 25.9h3.6v1.5h-3.6zM108.5 35.1h1.5v3.5h-1.5zM108.5 22.4h1.5v3.5h-1.5zM121.2 22.4h1.5v3.5h-1.5zM121.2 35.1h1.5v3.5h-1.5zM58.5 56.4h3.6v1.5h-3.6zM58.5 41.1h3.6v1.6h-3.6zM108.5 52.8h1.5v3.6h-1.5zM121.2 52.8h1.5v3.6h-1.5zM58.5 71.6h3.6v1.6h-3.6zM108.5 65.5h1.5v3.6h-1.5zM121.2 65.5h1.5v3.6h-1.5z"/>
<path d="M58.5 86.9h3.6v1.5h-3.6zM108.5 83.3h1.5v3.6h-1.5zM108.5 96h1.5v3.6h-1.5zM121.2 96h1.5v3.6h-1.5zM121.2 83.3h1.5v3.6h-1.5zM58.5 117.3h3.6v1.6h-3.6zM58.5 102.1h3.6v1.5h-3.6zM108.5 113.8h1.5v3.5h-1.5zM121.2 113.8h1.5v3.5h-1.5zM58.5 132.6h3.6v1.5h-3.6zM108.5 126.5h1.5v3.5h-1.5zM121.2 126.5h1.5v3.5h-1.5z"/>
<path d="M58.5 147.8h3.6v1.6h-3.6zM108.5 157h1.5v3.5h-1.5zM108.5 144.3h1.5v3.5h-1.5zM121.2 144.3h1.5v3.5h-1.5zM121.2 157h1.5v3.5h-1.5zM58.5 163.1h3.6v1.5h-3.6z"/>
</g>
<g fill="none" stroke="#840000" stroke-width=".25">
<path d="M35.6 31.8h5v5h-5zM66.7 24.1h10.1v20.4h-10.1zM68.7 28.6h1.3l-.7 1.2zM68.7 38.7h1.3M68.7 29.8h1.3M69.3 38.7l.7 1.3h-1.3zM73.2 38.1l2.5 1.3-2.5 1.2zM73.2 27.9l2.5 1.3-2.5 1.3zM76.5 39.4h.5M76.5 29.2h.6M113.3 27.4h1M113.7 26.9h3.8"/>
<path d="M113.7 39.6h3.8M115.1 27.4h1M116.8 27.4h1.1M66.7 54.6h10.1v20.3h-10.1zM68.7 59.1h1.3l-.7 1.2zM73.2 58.4l2.5 1.3-2.5 1.3zM76.5 59.7h.6M113.3 57.9h1M113.3 40.1h1M113.7 57.4h3.8M115.1 57.9h1M115.1 40.1h1"/>
<path d="M116.8 57.9h1.1M116.8 40.1h1.1M35.6 62.2h5v5.1h-5zM68.7 69.2h1.3M68.7 60.3h1.3M69.3 69.2l.7 1.3h-1.3zM73.2 68.6l2.5 1.3-2.5 1.2zM76.5 69.9h.5M113.3 70.6h1M113.7 70.1h3.8M115.1 70.6h1M116.8 70.6h1.1"/>
<path d="M35.6 92.7h5v5.1h-5zM66.7 85.1h10.1v20.3h-10.1zM68.7 89.5h1.3l-.7 1.3zM68.7 99.7h1.3M68.7 90.8h1.3M69.3 99.7l.7 1.3h-1.3zM73.2 99.1l2.5 1.2-2.5 1.3zM73.2 88.9l2.5 1.3-2.5 1.2zM76.5 90.2h.6M113.3 88.4h1M113.7 87.9h3.8M115.1 88.4h1"/>
<path d="M116.8 88.4h1.1M66.7 115.6h10.1v20.3h-10.1zM73.2 119.4l2.5 1.3-2.5 1.2zM76.5 100.3h.5M113.3 118.9h1M113.3 101.1h1M113.7 118.4h3.8M113.7 100.6h3.8M115.1 118.9h1M115.1 101.1h1M116.8 118.9h1.1M116.8 101.1h1.1"/>
<path d="M35.6 123.2h5v5.1h-5zM68.7 120h1.3l-.7 1.3zM68.7 130.2h1.3M68.7 121.3h1.3M69.3 130.2l.7 1.2h-1.3zM73.2 129.5l2.5 1.3-2.5 1.3zM76.5 130.8h.5M76.5 120.7h.6M113.3 131.6h1M113.7 131.1h3.8M115.1 131.6h1M116.8 131.6h1.1"/>
<path d="M35.6 153.7h5v5.1h-5zM66.7 146.1h10.1v20.3h-10.1zM68.7 150.5h1.3l-.7 1.3zM68.7 151.8h1.3M73.2 149.9l2.5 1.2-2.5 1.3zM76.5 151.1h.6M113.3 149.4h1M113.7 148.8h3.8M115.1 149.4h1M116.8 149.4h1.1M68.7 160.7h1.3M69.3 160.7l.7 1.2h-1.3z"/>
<path d="M73.2 160l2.5 1.3-2.5 1.3zM76.5 161.3h.5M113.3 162.1h1M113.7 161.5h3.8M115.1 162.1h1M116.8 162.1h1.1M107.3 180.3h15.3v12.7h-15.3z"/>
<circle cx="76.1" cy="29.2" r=".36"/>
<circle cx="76.1" cy="39.4" r=".36"/>
<circle cx="115.6" cy="28.3" r="2.79"/>
<circle cx="76.1" cy="59.7" r=".36"/>
<circle cx="115.6" cy="58.8" r="2.79"/>
<circle cx="115.6" cy="41" r="2.79"/>
<circle cx="76.1" cy="69.9" r=".36"/>
<circle cx="115.6" cy="71.5" r="2.79"/>
<circle cx="76.1" cy="90.2" r=".36"/>
<circle cx="115.6" cy="89.3" r="2.79"/>
<circle cx="76.1" cy="100.3" r=".36"/>
<circle cx="115.6" cy="119.8" r="2.79"/>
<circle cx="115.6" cy="102" r="2.79"/>
<circle cx="76.1" cy="130.8" r=".36"/>
<circle cx="76.1" cy="120.7" r=".36"/>
<circle cx="115.6" cy="132.5" r="2.79"/>
<circle cx="76.1" cy="151.1" r=".36"/>
<circle cx="115.6" cy="150.2" r="2.79"/>
<circle cx="76.1" cy="161.3" r=".36"/>
<circle cx="115.6" cy="162.9" r="2.79"/>
</g>
<g fill="#840000" stroke="#840000" stroke-width=".18">
<path d="M115.6 58.2l.4 1h-.8z"/>
<path d="M115.6 27.7l.4 1h-.8z"/>
<path d="M115.6 149.6l.4 1h-.8z"/>
<path d="M115.6 40.4l.4 1h-.8z"/>
<path d="M115.6 119.1l.4 1h-.8z"/>
<path d="M115.6 131.8l.4 1h-.8z"/>
<path d="M115.6 162.3l.4 1h-.8z"/>
<path d="M115.6 70.9l.4 1h-.8z"/>
<path d="M115.6 88.6l.4 1.1h-.8z"/>
<path d="M115.6 101.3l.4 1.1h-.8z"/>
<circle cx="117.3" cy="59.7" r=".25"/>
<circle cx="113.8" cy="59.7" r=".25"/>
<circle cx="117.3" cy="29.2" r=".25"/>
<circle cx="113.8" cy="29.2" r=".25"/>
<circle cx="117.3" cy="151.1" r=".25"/>
<circle cx="113.8" cy="151.1" r=".25"/>
<circle cx="117.3" cy="41.9" r=".25"/>
<circle cx="113.8" cy="41.9" r=".25"/>
<circle cx="117.3" cy="120.6" r=".25"/>
<circle cx="113.8" cy="120.6" r=".25"/>
<circle cx="117.3" cy="133.3" r=".25"/>
<circle cx="113.8" cy="133.3" r=".25"/>
<circle cx="117.3" cy="163.8" r=".25"/>
<circle cx="113.8" cy="163.8" r=".25"/>
<circle cx="117.3" cy="72.4" r=".25"/>
<circle cx="113.8" cy="72.4" r=".25"/>
<circle cx="117.3" cy="90.2" r=".25"/>
<circle cx="113.8" cy="90.2" r=".25"/>
<circle cx="117.3" cy="102.9" r=".25"/>
<circle cx="113.8" cy="102.9" r=".25"/>
</g>
<g fill="#ffffc2" stroke="#ffffc2" stroke-width=".18">
<path d="M35.6 62.2h5v5.1h-5z"/>
<path d="M35.6 31.8h5v5h-5z"/>
<path d="M66.7 85.1h10.1v20.3h-10.1z"/>
<path d="M66.7 54.6h10.1v20.3h-10.1z"/>
<path d="M66.7 115.6h10.1v20.3h-10.1z"/>
<path d="M66.7 24.1h10.1v20.4h-10.1z"/>
<path d="M35.6 92.7h5v5.1h-5z"/>
<path d="M35.6 123.2h5v5.1h-5z"/>
<path d="M35.6 153.7h5v5.1h-5z"/>
<path d="M66.7 146.1h10.1v20.3h-10.1z"/>
<path d="M107.3 180.3h15.3v12.7h-15.3z"/>
</g>
<g fill="none" stroke="#009600" stroke-width=".18">
<path d="M92.7 17.1h-2.5v137.8h19v1.3M154.9 17.1h-2.5v137.8h-36.8v1.3M26 35.6h5.7M31.7 33h-5.7v157.5h78.8M44.4 35.6h3.2v1.2h16.5M57.8 26.7h-2.6v156.2h49.6M62.9 26.7h1.2M64.1 31.8h-16.5v1.2h-3.2M71.8 21.6v-1.3h37.4v1.3M79.4 39.4h22.8v2.5h8.3M79.4 29.2h31.1M80 20.3v2.6h1.3"/>
<path d="M86.4 22.9h1.2v148.6M90.2 33h19v1.3M109.2 26.7v2.5M109.2 39.4v2.5M120.6 29.2h8.3M121.9 20.3v1.3M121.9 26.7v2.5M121.9 33v1.3M121.9 39.4v2.5M152.4 20.3h-36.8v1.3M152.4 33h-36.8v1.3M55.2 57.2h2.6"/>
<path d="M55.2 41.9h2.6M62.9 57.2h1.2M62.9 41.9h1.2M71.8 52.1v-1.3h37.4v1.3M71.8 47v1.3h15.8M79.4 59.7h31.1M80 50.8v2.5h1.3M86.4 53.3h1.2M109.2 57.2v2.5M120.6 41.9h8.3M120.6 59.7h8.3M121.9 50.8v1.3"/>
<path d="M121.9 57.2v2.5M152.4 50.8h-36.8v1.3M26 63.5h5.7M26 66h5.7M44.4 66h3.2v1.3h16.5M55.2 72.4h2.6M62.9 72.4h1.2M64.1 62.2h-16.5v1.3h-3.2M71.8 77.5v1.2h15.8M79.4 69.9h22.8v2.5h8.3M90.2 63.5h19v1.3M109.2 69.9v2.5"/>
<path d="M120.6 72.4h8.3M121.9 63.5v1.3M121.9 69.9v2.5M152.4 63.5h-36.8v1.3M26 96.5h5.7M26 94h5.7M44.4 96.5h3.2v1.3h16.5M55.2 87.6h2.6M62.9 87.6h1.2M64.1 92.7h-16.5v1.3h-3.2M71.8 82.6v-1.3h37.4v1.3M79.4 90.2h31.1"/>
<path d="M80 81.3v2.5h1.3M86.4 83.8h1.2M90.2 94h19v1.3M109.2 87.6v2.6M120.6 90.2h8.3M121.9 81.3v1.3M121.9 87.6v2.6M121.9 94v1.3M152.4 81.3h-36.8v1.3M152.4 94h-36.8v1.3M55.2 102.9h2.6M55.2 118.1h2.6"/>
<path d="M62.9 102.9h1.2M62.9 118.1h1.2M71.8 113v-1.2h37.4v1.2M71.8 108v1.2h15.8M79.4 100.3h22.8v2.6h8.3M80 111.8v2.5h1.3M86.4 114.3h1.2M109.2 100.3v2.6M109.2 118.1v2.6M120.6 102.9h8.3M121.9 100.3v2.6M121.9 111.8v1.2"/>
<path d="M121.9 118.1v2.6M152.4 111.8h-36.8v1.2M26 127h5.7M26 124.5h5.7M44.4 127h3.2v1.3h16.5M55.2 133.4h2.6M62.9 133.4h1.2M64.1 123.2h-16.5v1.3h-3.2M71.8 138.4v1.3h15.8M79.4 130.8h22.8v2.6h8.3M79.4 120.7h31.1M90.2 124.5h19v1.2"/>
<path d="M109.2 130.8v2.6M120.6 133.4h8.3M120.6 120.7h8.3M121.9 124.5v1.2M121.9 130.8v2.6M152.4 124.5h-36.8v1.2M26 157.5h5.7M26 154.9h5.7M44.4 157.5h3.2v1.3h16.5M55.2 148.6h2.6M62.9 148.6h1.2M64.1 153.7h-16.5v1.2h-3.2"/>
<path d="M71.8 143.5v-1.3h37.4v1.3M79.4 151.1h31.1M80 142.2v2.6h1.3M86.4 144.8h1.2M109.2 148.6v2.5M120.6 151.1h8.3M121.9 142.2v1.3M121.9 148.6v2.5M121.9 154.9v1.3M152.4 142.2h-36.8v1.3M55.2 163.8h2.6M62.9 163.8h1.2"/>
<path d="M71.8 168.9v1.3h15.8M79.4 161.3h22.8v2.5h8.3M109.2 161.3v2.5M120.6 163.8h8.3M121.9 161.3v2.5M94 182.9v1.3M94 189.2v1.3M104.8 188h-2.6v2.5M125.1 190.5h14v1.3M125.1 188h2.5v2.5M127.6 182.9v2.5h-2.5M130.8 182.9v1.3"/>
<path d="M130.8 189.2v1.3M139.1 181.6v1.3h-14"/>
</g>
<g fill="#009600" stroke="#009600" stroke-width=".18">
<circle cx="121.9" cy="63.5" r=".46"/>
<circle cx="109.2" cy="90.2" r=".46"/>
<circle cx="121.9" cy="90.2" r=".46"/>
<circle cx="109.2" cy="72.4" r=".46"/>
<circle cx="121.9" cy="81.3" r=".46"/>
<circle cx="80" cy="20.3" r=".46"/>
<circle cx="90.2" cy="81.3" r=".46"/>
<circle cx="87.6" cy="78.7" r=".46"/>
<circle cx="87.6" cy="83.8" r=".46"/>
<circle cx="80" cy="81.3" r=".46"/>
<circle cx="90.2" cy="33" r=".46"/>
<circle cx="90.2" cy="20.3" r=".46"/>
<circle cx="90.2" cy="50.8" r=".46"/>
<circle cx="87.6" cy="53.3" r=".46"/>
<circle cx="80" cy="50.8" r=".46"/>
<circle cx="87.6" cy="48.3" r=".46"/>
<circle cx="55.2" cy="57.2" r=".46"/>
<circle cx="55.2" cy="41.9" r=".46"/>
<circle cx="26" cy="35.6" r=".46"/>
<circle cx="90.2" cy="63.5" r=".46"/>
<circle cx="109.2" cy="59.7" r=".46"/>
<circle cx="109.2" cy="29.2" r=".46"/>
<circle cx="121.9" cy="29.2" r=".46"/>
<circle cx="121.9" cy="33" r=".46"/>
<circle cx="109.2" cy="41.9" r=".46"/>
<circle cx="121.9" cy="20.3" r=".46"/>
<circle cx="152.4" cy="63.5" r=".46"/>
<circle cx="152.4" cy="50.8" r=".46"/>
<circle cx="152.4" cy="81.3" r=".46"/>
<circle cx="152.4" cy="94" r=".46"/>
<circle cx="121.9" cy="50.8" r=".46"/>
<circle cx="121.9" cy="41.9" r=".46"/>
<circle cx="152.4" cy="33" r=".46"/>
<circle cx="152.4" cy="20.3" r=".46"/>
<circle cx="121.9" cy="59.7" r=".46"/>
<circle cx="26" cy="127" r=".46"/>
<circle cx="26" cy="124.5" r=".46"/>
<circle cx="55.2" cy="118.1" r=".46"/>
<circle cx="26" cy="96.5" r=".46"/>
<circle cx="26" cy="94" r=".46"/>
<circle cx="26" cy="63.5" r=".46"/>
<circle cx="26" cy="66" r=".46"/>
<circle cx="80" cy="142.2" r=".46"/>
<circle cx="55.2" cy="72.4" r=".46"/>
<circle cx="55.2" cy="102.9" r=".46"/>
<circle cx="55.2" cy="87.6" r=".46"/>
<circle cx="90.2" cy="142.2" r=".46"/>
<circle cx="87.6" cy="139.7" r=".46"/>
<circle cx="55.2" cy="133.4" r=".46"/>
<circle cx="26" cy="157.5" r=".46"/>
<circle cx="26" cy="154.9" r=".46"/>
<circle cx="87.6" cy="144.8" r=".46"/>
<circle cx="55.2" cy="163.8" r=".46"/>
<circle cx="55.2" cy="148.6" r=".46"/>
<circle cx="87.6" cy="109.2" r=".46"/>
<circle cx="90.2" cy="94" r=".46"/>
<circle cx="80" cy="111.8" r=".46"/>
<circle cx="90.2" cy="124.5" r=".46"/>
<circle cx="87.6" cy="114.3" r=".46"/>
<circle cx="90.2" cy="111.8" r=".46"/>
<circle cx="127.6" cy="182.9" r=".46"/>
<circle cx="102.2" cy="190.5" r=".46"/>
<circle cx="130.8" cy="182.9" r=".46"/>
<circle cx="130.8" cy="190.5" r=".46"/>
<circle cx="127.6" cy="190.5" r=".46"/>
<circle cx="94" cy="190.5" r=".46"/>
<circle cx="94" cy="182.9" r=".46"/>
<circle cx="87.6" cy="170.2" r=".46"/>
<circle cx="152.4" cy="142.2" r=".46"/>
<circle cx="152.4" cy="111.8" r=".46"/>
<circle cx="152.4" cy="124.5" r=".46"/>
<circle cx="121.9" cy="120.7" r=".46"/>
<circle cx="121.9" cy="124.5" r=".46"/>
<circle cx="109.2" cy="120.7" r=".46"/>
<circle cx="121.9" cy="72.4" r=".46"/>
<circle cx="121.9" cy="94" r=".46"/>
<circle cx="121.9" cy="102.9" r=".46"/>
<circle cx="121.9" cy="111.8" r=".46"/>
<circle cx="109.2" cy="102.9" r=".46"/>
<circle cx="109.2" cy="163.8" r=".46"/>
<circle cx="109.2" cy="151.1" r=".46"/>
<circle cx="109.2" cy="133.4" r=".46"/>
<circle cx="121.9" cy="154.9" r=".46"/>
<circle cx="121.9" cy="142.2" r=".46"/>
<circle cx="121.9" cy="133.4" r=".46"/>
<circle cx="121.9" cy="151.1" r=".46"/>
<circle cx="121.9" cy="163.8" r=".46"/>
</g>
<use href="#words"/>
</svg>
